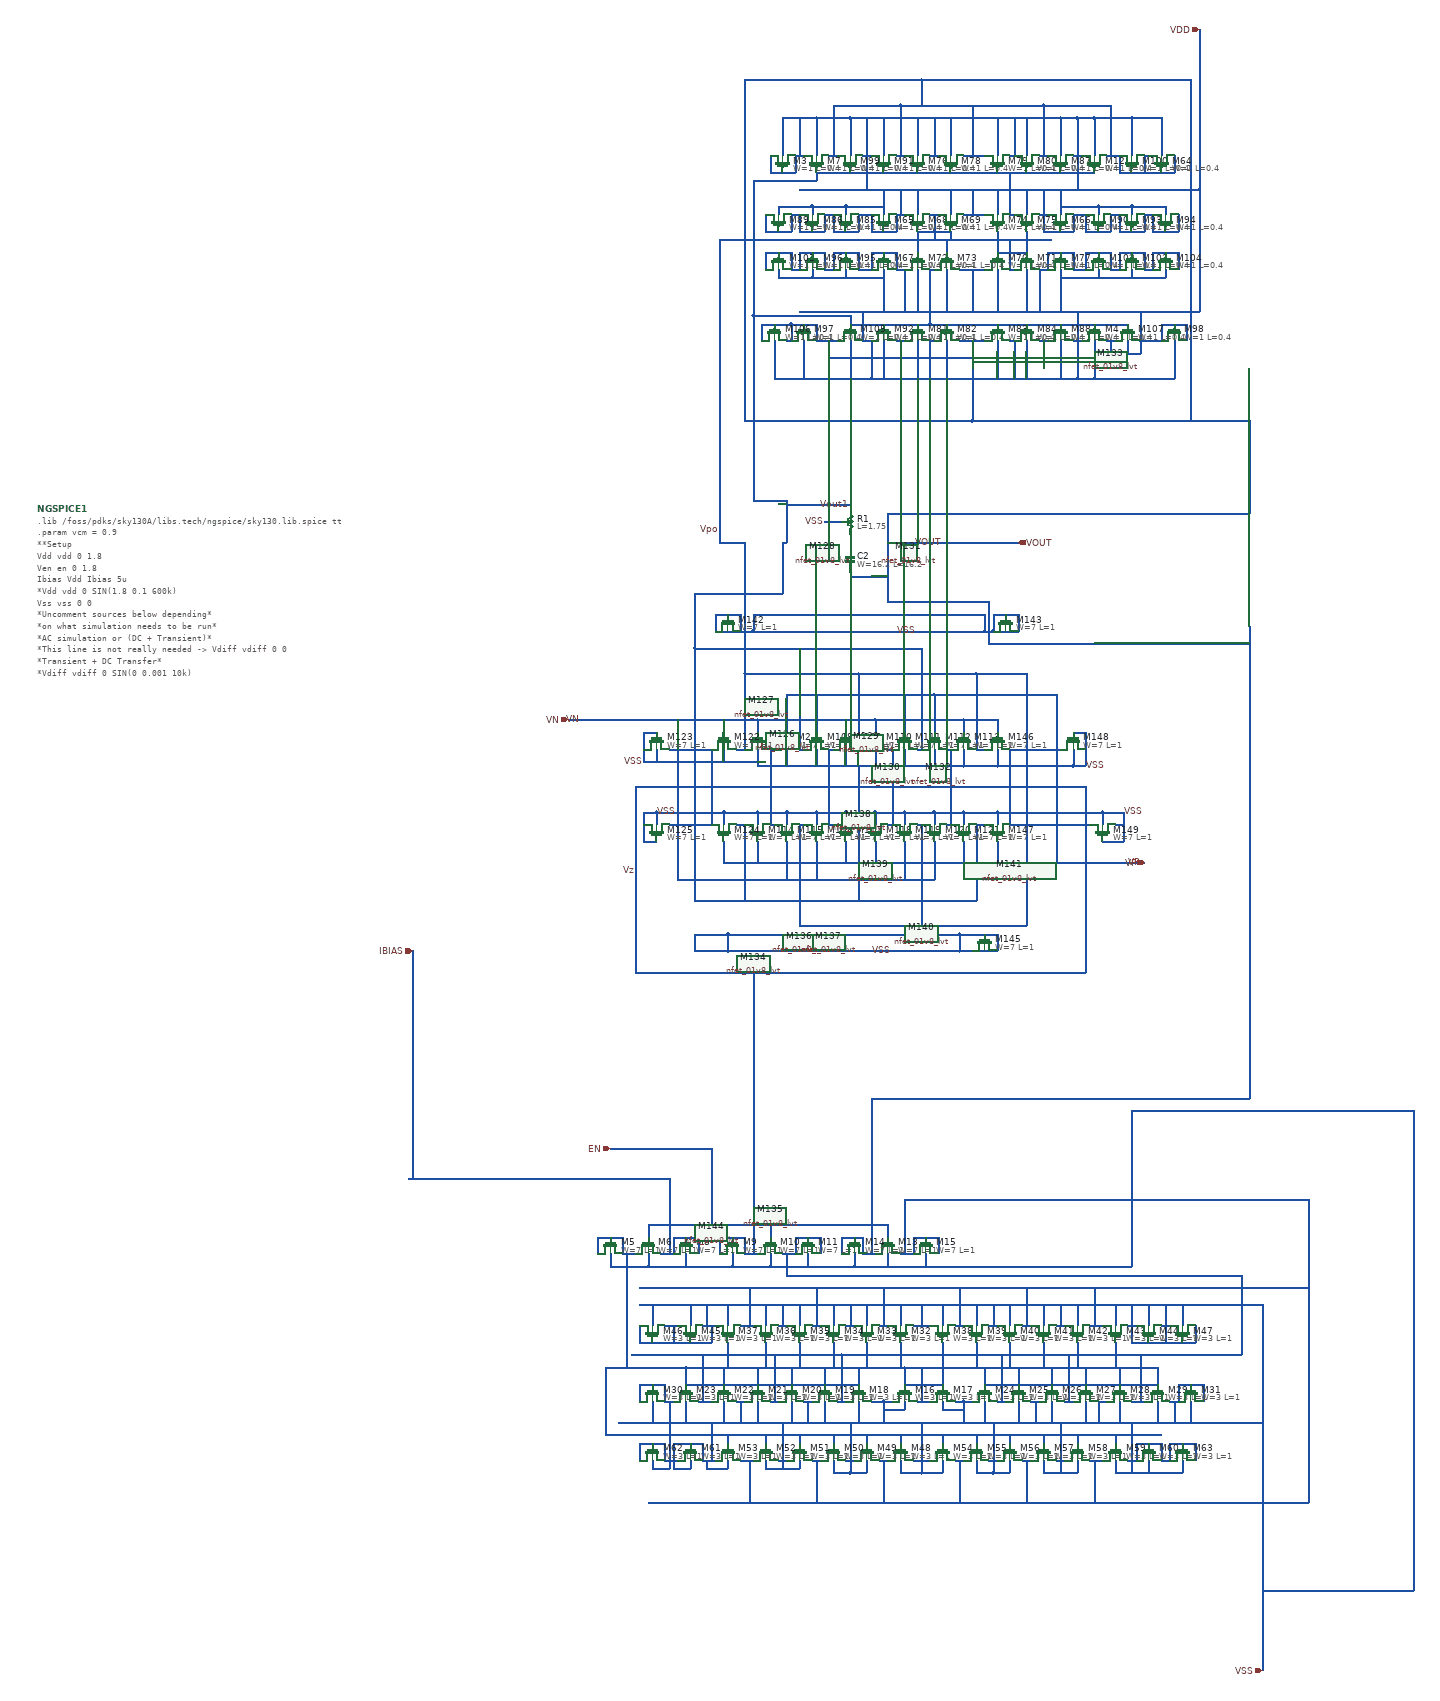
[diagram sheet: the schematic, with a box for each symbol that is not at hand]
v {xschem version=3.4.8RC file_version=1.2}
G {}
K {}
V {}
S {}
F {}
E {}
N -560 -780 -560 -720 {lab=Vpo}
N -400 -780 -400 -720 {lab=Vout1}
N -920 -300 -880 -300 {lab=VN}
N -560 -820 -560 -780 {lab=Vpo}
N -400 -820 -400 -780 {lab=Vout1}
N -1290 250 -1290 490 {lab=IBIAS}
N -160 -760 -160 -680 {lab=VOUT}
N -400 -810 -250 -810 {lab=Vout1}
N 70 -720 150 -720 {lab=VOUT}
N -30 -720 70 -720 {lab=VOUT}
N -160 -720 -30 -720 {lab=VOUT}
N -1290 490 -1290 530 {lab=IBIAS}
N -160 -780 -160 -760 {lab=VOUT}
N -160 -680 -160 -630 {lab=VOUT}
N -250 -730 -250 -710 {lab=#net1}
N -250 -650 -250 -640 {lab=VOUT}
N -250 -640 -160 -640 {lab=VOUT}
N -250 -810 -250 -800 {lab=Vout1}
N -250 -740 -250 -730 {lab=#net1}
N 420 40 440 40 {lab=VP}
N 440 40 450 40 {lab=VP}
N -310 -770 -270 -770 {lab=VSS}
N -850 930 -850 970 {lab=#net2}
N -850 930 -820 930 {lab=#net2}
N -820 930 -790 930 {lab=#net2}
N -790 930 -790 970 {lab=#net2}
N -790 970 -760 970 {lab=#net2}
N -700 970 -670 970 {lab=IBIAS}
N -670 930 -670 970 {lab=IBIAS}
N -670 930 -640 930 {lab=IBIAS}
N -640 930 -610 930 {lab=IBIAS}
N -610 930 -610 970 {lab=IBIAS}
N -560 930 -560 970 {lab=Vz}
N -560 930 -530 930 {lab=Vz}
N -530 930 -500 930 {lab=Vz}
N -500 930 -500 970 {lab=Vz}
N -500 970 -470 970 {lab=Vz}
N -410 970 -380 970 {lab=#net3}
N -380 930 -380 970 {lab=#net3}
N -380 930 -350 930 {lab=#net3}
N -350 930 -320 930 {lab=#net3}
N -320 930 -320 970 {lab=#net3}
N -250 930 -220 930 {lab=VOUT}
N -220 930 -220 970 {lab=VOUT}
N -220 970 -190 970 {lab=VOUT}
N -130 970 -100 970 {lab=#net4}
N -100 930 -100 970 {lab=#net4}
N -100 930 -70 930 {lab=#net4}
N -70 930 -40 930 {lab=#net4}
N -40 930 -40 970 {lab=#net4}
N -730 900 -350 900 {lab=EN}
N -350 900 -160 900 {lab=EN}
N -160 900 -160 930 {lab=EN}
N -440 900 -440 930 {lab=EN}
N -90 1320 -60 1320 {lab=#net2}
N -820 720 -730 720 {lab=EN}
N -120 1240 -40 1240 {lab=#net2}
N -30 1240 -30 1280 {lab=#net2}
N -40 1240 -30 1240 {lab=#net2}
N -120 1240 -120 1280 {lab=#net2}
N -80 1240 -80 1320 {lab=#net2}
N -120 1280 -80 1280 {lab=#net2}
N -80 1280 -30 1280 {lab=#net2}
N -170 1320 -150 1320 {lab=VSS}
N 0 1320 20 1320 {lab=VSS}
N -200 1320 -170 1320 {lab=VSS}
N -280 1320 -260 1320 {lab=#net3}
N -360 1320 -340 1320 {lab=VSS}
N -440 1320 -420 1320 {lab=#net3}
N -520 1320 -500 1320 {lab=VSS}
N -610 1320 -580 1320 {lab=#net3}
N -640 1240 -120 1240 {lab=#net2}
N -230 1240 -230 1280 {lab=#net2}
N -310 1240 -310 1280 {lab=#net2}
N -390 1240 -390 1280 {lab=#net2}
N -470 1240 -470 1280 {lab=#net2}
N -550 1240 -550 1280 {lab=#net2}
N -640 1240 -640 1280 {lab=#net2}
N -640 1280 -230 1280 {lab=#net2}
N -270 1210 -270 1320 {lab=#net3}
N -330 1210 -270 1210 {lab=#net3}
N 20 1320 40 1320 {lab=VSS}
N 100 1320 120 1320 {lab=#net3}
N 180 1320 200 1320 {lab=VSS}
N 260 1320 280 1320 {lab=#net3}
N 340 1320 360 1320 {lab=VSS}
N 420 1320 450 1320 {lab=#net3}
N -270 1210 500 1210 {lab=#net3}
N -770 1210 -330 1210 {lab=#net3}
N 110 1210 110 1320 {lab=#net3}
N -120 840 -120 970 {lab=#net4}
N -120 840 250 840 {lab=#net4}
N -600 1210 -600 1320 {lab=#net3}
N 440 1210 440 1320 {lab=#net3}
N -30 1240 480 1240 {lab=#net2}
N 480 1240 480 1280 {lab=#net2}
N 390 1240 390 1280 {lab=#net2}
N 310 1240 310 1280 {lab=#net2}
N 230 1240 230 1280 {lab=#net2}
N 150 1240 150 1280 {lab=#net2}
N 70 1250 70 1280 {lab=#net2}
N 70 1240 70 1250 {lab=#net2}
N 70 1280 480 1280 {lab=#net2}
N -430 1210 -430 1320 {lab=#net3}
N 270 1210 270 1320 {lab=#net3}
N -690 1320 -670 1320 {lab=VSS}
N -690 1280 -690 1320 {lab=VSS}
N -720 1280 -690 1280 {lab=VSS}
N -750 1280 -720 1280 {lab=VSS}
N -750 1280 -750 1320 {lab=VSS}
N 510 1320 530 1320 {lab=VSS}
N 530 1280 530 1320 {lab=VSS}
N 530 1280 560 1280 {lab=VSS}
N 560 1280 590 1280 {lab=VSS}
N 590 1280 590 1320 {lab=VSS}
N -830 1240 -640 1240 {lab=#net2}
N -830 1240 -830 1400 {lab=#net2}
N -830 1400 490 1400 {lab=#net2}
N -730 900 -730 930 {lab=EN}
N -480 620 -480 970 {lab=Vz}
N -200 600 -200 970 {lab=VOUT}
N -580 720 -580 900 {lab=EN}
N -730 720 -580 720 {lab=EN}
N -1300 790 -680 790 {lab=IBIAS}
N -680 790 -680 970 {lab=IBIAS}
N -780 970 -780 1240 {lab=#net2}
N -540 1180 -540 1240 {lab=#net2}
N -450 1180 -450 1240 {lab=#net2}
N -370 1180 -370 1240 {lab=#net2}
N -290 1180 -290 1240 {lab=#net2}
N -210 1180 -210 1240 {lab=#net2}
N -130 1180 -130 1240 {lab=#net2}
N -30 1180 -30 1240 {lab=#net2}
N 50 1180 50 1240 {lab=#net2}
N 130 1180 130 1240 {lab=#net2}
N 210 1180 210 1240 {lab=#net2}
N 290 1180 290 1240 {lab=#net2}
N 380 1180 380 1240 {lab=#net2}
N -540 1400 -540 1420 {lab=#net2}
N -450 1400 -450 1420 {lab=#net2}
N -370 1400 -370 1420 {lab=#net2}
N -290 1400 -290 1420 {lab=#net2}
N -210 1400 -210 1420 {lab=#net2}
N -130 1400 -130 1420 {lab=#net2}
N -30 1400 -30 1420 {lab=#net2}
N 50 1400 50 1420 {lab=#net2}
N 130 1400 130 1420 {lab=#net2}
N 210 1400 210 1420 {lab=#net2}
N 290 1400 290 1420 {lab=#net2}
N 380 1400 380 1420 {lab=#net2}
N -690 1140 -660 1140 {lab=VSS}
N -600 1140 -570 1140 {lab=VSS}
N -510 1140 -480 1140 {lab=#net4}
N -420 1140 -400 1140 {lab=VSS}
N -340 1140 -320 1140 {lab=#net4}
N -260 1140 -240 1140 {lab=VSS}
N -180 1140 -160 1140 {lab=#net4}
N -100 1140 -60 1140 {lab=VSS}
N 0 1140 20 1140 {lab=#net4}
N 80 1140 100 1140 {lab=VSS}
N 160 1140 180 1140 {lab=#net4}
N 240 1140 260 1140 {lab=VSS}
N 320 1140 350 1140 {lab=#net4}
N 410 1140 430 1140 {lab=VSS}
N 490 1140 510 1140 {lab=VSS}
N 420 1140 420 1180 {lab=VSS}
N 420 1180 460 1180 {lab=VSS}
N 460 1180 500 1180 {lab=VSS}
N 500 1140 500 1180 {lab=VSS}
N 500 1180 540 1180 {lab=VSS}
N 540 1180 570 1180 {lab=VSS}
N 570 1140 570 1180 {lab=VSS}
N 490 1460 510 1460 {lab=VSS}
N 510 1420 510 1460 {lab=VSS}
N 510 1420 540 1420 {lab=VSS}
N 540 1420 570 1420 {lab=VSS}
N 570 1420 570 1460 {lab=VSS}
N 490 1420 490 1460 {lab=VSS}
N 460 1420 490 1420 {lab=VSS}
N 430 1420 460 1420 {lab=VSS}
N 430 1420 430 1460 {lab=VSS}
N 410 1460 430 1460 {lab=VSS}
N 320 1460 350 1460 {lab=#net4}
N 240 1460 260 1460 {lab=VSS}
N 160 1460 180 1460 {lab=#net4}
N 80 1460 100 1460 {lab=VSS}
N 0 1460 20 1460 {lab=#net4}
N -100 1460 -60 1460 {lab=VSS}
N -180 1460 -160 1460 {lab=#net4}
N -260 1460 -240 1460 {lab=VSS}
N -340 1460 -320 1460 {lab=#net4}
N -420 1460 -400 1460 {lab=VSS}
N -510 1460 -480 1460 {lab=#net4}
N -600 1460 -570 1460 {lab=VSS}
N -690 1460 -660 1460 {lab=VSS}
N -600 1420 -600 1460 {lab=VSS}
N -630 1420 -600 1420 {lab=VSS}
N -670 1420 -630 1420 {lab=VSS}
N -670 1420 -670 1460 {lab=VSS}
N -690 1420 -690 1460 {lab=VSS}
N -720 1420 -690 1420 {lab=VSS}
N -750 1420 -720 1420 {lab=VSS}
N -750 1420 -750 1460 {lab=VSS}
N -800 1370 730 1370 {lab=VSS}
N -680 1320 -680 1370 {lab=VSS}
N -680 1370 -680 1460 {lab=VSS}
N -720 1320 -720 1370 {lab=VSS}
N -640 1320 -640 1370 {lab=VSS}
N -550 1320 -550 1370 {lab=VSS}
N -510 1320 -510 1370 {lab=VSS}
N -470 1320 -470 1370 {lab=VSS}
N -750 1140 -750 1180 {lab=VSS}
N -750 1180 -720 1180 {lab=VSS}
N -720 1180 -670 1180 {lab=VSS}
N -670 1140 -670 1180 {lab=VSS}
N -680 1180 -630 1180 {lab=VSS}
N -630 1180 -580 1180 {lab=VSS}
N -580 1140 -580 1180 {lab=VSS}
N -720 1460 -720 1480 {lab=VSS}
N -720 1480 -680 1480 {lab=VSS}
N -680 1460 -680 1480 {lab=VSS}
N -630 1460 -630 1480 {lab=VSS}
N -670 1480 -630 1480 {lab=VSS}
N -670 1460 -670 1480 {lab=VSS}
N -540 1460 -540 1480 {lab=VSS}
N -590 1480 -540 1480 {lab=VSS}
N -590 1460 -590 1480 {lab=VSS}
N -580 1370 -580 1460 {lab=VSS}
N -450 1460 -450 1480 {lab=VSS}
N -450 1480 -410 1480 {lab=VSS}
N -410 1460 -410 1480 {lab=VSS}
N -410 1370 -410 1460 {lab=VSS}
N -350 1320 -350 1370 {lab=VSS}
N -390 1320 -390 1370 {lab=VSS}
N -370 1460 -370 1480 {lab=VSS}
N -410 1480 -370 1480 {lab=VSS}
N -250 1370 -250 1460 {lab=VSS}
N -310 1320 -310 1370 {lab=VSS}
N -250 1460 -250 1490 {lab=VSS}
N -290 1490 -250 1490 {lab=VSS}
N -290 1460 -290 1490 {lab=VSS}
N -250 1490 -210 1490 {lab=VSS}
N -210 1460 -210 1490 {lab=VSS}
N -230 1320 -230 1370 {lab=VSS}
N -170 1320 -170 1370 {lab=VSS}
N -120 1320 -120 1340 {lab=VSS}
N -170 1340 -120 1340 {lab=VSS}
N -80 1370 -80 1460 {lab=VSS}
N -130 1460 -130 1490 {lab=VSS}
N -130 1490 -80 1490 {lab=VSS}
N -80 1460 -80 1490 {lab=VSS}
N -80 1490 -30 1490 {lab=VSS}
N -30 1460 -30 1490 {lab=VSS}
N -30 1320 -30 1340 {lab=VSS}
N -30 1340 20 1340 {lab=VSS}
N 20 1320 20 1340 {lab=VSS}
N 20 1340 20 1370 {lab=VSS}
N 90 1370 90 1460 {lab=VSS}
N 50 1460 50 1490 {lab=VSS}
N 50 1490 90 1490 {lab=VSS}
N 90 1460 90 1490 {lab=VSS}
N 130 1460 130 1490 {lab=VSS}
N 90 1490 130 1490 {lab=VSS}
N 70 1320 70 1370 {lab=VSS}
N 190 1320 190 1370 {lab=VSS}
N 150 1320 150 1370 {lab=VSS}
N 250 1370 250 1460 {lab=VSS}
N 210 1460 210 1490 {lab=VSS}
N 210 1490 290 1490 {lab=VSS}
N 290 1460 290 1490 {lab=VSS}
N 250 1460 250 1490 {lab=VSS}
N 230 1320 230 1370 {lab=VSS}
N 310 1320 310 1370 {lab=VSS}
N 390 1320 390 1370 {lab=VSS}
N 480 1320 480 1370 {lab=VSS}
N 520 1320 520 1370 {lab=VSS}
N 340 1320 340 1370 {lab=VSS}
N 420 1370 420 1460 {lab=VSS}
N 380 1460 380 1490 {lab=VSS}
N 380 1490 540 1490 {lab=VSS}
N 540 1460 540 1490 {lab=VSS}
N 460 1460 460 1490 {lab=VSS}
N -750 1090 660 1090 {lab=VSS}
N 730 1090 730 1370 {lab=VSS}
N 660 1090 730 1090 {lab=VSS}
N 730 1370 730 1900 {lab=VSS}
N -720 1090 -720 1140 {lab=VSS}
N -590 1090 -590 1140 {lab=VSS}
N -630 1090 -630 1140 {lab=VSS}
N -540 1090 -540 1140 {lab=VSS}
N -410 1090 -410 1140 {lab=VSS}
N -450 1090 -450 1140 {lab=VSS}
N -370 1090 -370 1140 {lab=VSS}
N -290 1090 -290 1140 {lab=VSS}
N -250 1090 -250 1140 {lab=VSS}
N -210 1090 -210 1140 {lab=VSS}
N -130 1090 -130 1140 {lab=VSS}
N -80 1090 -80 1140 {lab=VSS}
N -30 1090 -30 1140 {lab=VSS}
N 50 1090 50 1140 {lab=VSS}
N 90 1090 90 1140 {lab=VSS}
N 130 1090 130 1140 {lab=VSS}
N 210 1090 210 1140 {lab=VSS}
N 250 1090 250 1140 {lab=VSS}
N 290 1090 290 1140 {lab=VSS}
N 380 1090 380 1140 {lab=VSS}
N 420 1090 420 1140 {lab=VSS}
N 460 1090 460 1140 {lab=VSS}
N 500 1090 500 1140 {lab=VSS}
N 540 1090 540 1140 {lab=VSS}
N 500 1210 660 1210 {lab=#net3}
N -400 1020 660 1020 {lab=#net3}
N -400 970 -400 1020 {lab=#net3}
N -730 1560 840 1560 {lab=#net4}
N 840 840 840 1560 {lab=#net4}
N 250 840 840 840 {lab=#net4}
N -750 1050 840 1050 {lab=#net4}
N -490 1050 -490 1140 {lab=#net4}
N -330 1050 -330 1140 {lab=#net4}
N -170 1050 -170 1140 {lab=#net4}
N 10 1050 10 1140 {lab=#net4}
N 170 1050 170 1140 {lab=#net4}
N 330 1050 330 1140 {lab=#net4}
N -490 1460 -490 1560 {lab=#net4}
N -330 1460 -330 1560 {lab=#net4}
N -170 1460 -170 1560 {lab=#net4}
N 10 1460 10 1560 {lab=#net4}
N 170 1460 170 1560 {lab=#net4}
N 330 1460 330 1560 {lab=#net4}
N -160 -630 -160 -600 {lab=VOUT}
N -200 600 -160 600 {lab=VOUT}
N -1290 530 -1290 790 {lab=IBIAS}
N 1090 630 1090 1770 {lab=VSS}
N 730 1770 1090 1770 {lab=VSS}
N -820 970 -820 1000 {lab=VSS}
N -820 1000 -730 1000 {lab=VSS}
N -730 970 -730 1000 {lab=VSS}
N -730 1000 -640 1000 {lab=VSS}
N -640 970 -640 1000 {lab=VSS}
N -640 1000 -530 1000 {lab=VSS}
N -530 970 -530 1000 {lab=VSS}
N -530 1000 -440 1000 {lab=VSS}
N -440 970 -440 1000 {lab=VSS}
N -440 1000 -350 1000 {lab=VSS}
N -350 970 -350 1000 {lab=VSS}
N -350 1000 -240 1000 {lab=VSS}
N -240 970 -240 1000 {lab=VSS}
N -240 1000 -160 1000 {lab=VSS}
N -160 970 -160 1000 {lab=VSS}
N -160 1000 -70 1000 {lab=VSS}
N -70 970 -70 1000 {lab=VSS}
N -70 1000 420 1000 {lab=VSS}
N 420 630 420 1000 {lab=VSS}
N 420 1460 420 1490 {lab=VSS}
N 560 1320 560 1370 {lab=VSS}
N 660 1210 680 1210 {lab=#net3}
N 680 1020 680 1210 {lab=#net3}
N 660 1020 680 1020 {lab=#net3}
N -270 930 -270 970 {lab=VOUT}
N -270 930 -250 930 {lab=VOUT}
N -60 -1500 -40 -1500 {lab=Vpo}
N 130 -1370 140 -1370 {lab=Vpo}
N -140 -1440 230 -1440 {lab=Vpo}
N 100 -1440 100 -1420 {lab=Vpo}
N -90 -1460 -90 -1440 {lab=Vpo}
N -90 -1440 -90 -1410 {lab=Vpo}
N -20 -1440 -20 -1410 {lab=Vpo}
N -370 -1560 580 -1560 {lab=VDD}
N -370 -1270 580 -1270 {lab=VDD}
N 580 -1560 580 -1270 {lab=VDD}
N 580 -1940 580 -1560 {lab=VDD}
N 100 -1460 100 -1440 {lab=Vpo}
N 170 -1460 170 -1440 {lab=Vpo}
N 170 -1440 170 -1420 {lab=Vpo}
N 130 -1500 140 -1500 {lab=Vout1}
N -60 -1370 -50 -1370 {lab=Vout1}
N 20 -1500 70 -1500 {lab=VDD}
N 40 -1560 40 -1500 {lab=VDD}
N -50 -1500 -50 -1460 {lab=Vpo}
N -50 -1460 -10 -1460 {lab=Vpo}
N -90 -1460 -50 -1460 {lab=Vpo}
N 100 -1560 100 -1500 {lab=VDD}
N 170 -1560 170 -1500 {lab=VDD}
N 100 -1420 100 -1410 {lab=Vpo}
N 170 -1420 170 -1410 {lab=Vpo}
N -90 -1370 -90 -1270 {lab=VDD}
N -20 -1370 -20 -1270 {lab=VDD}
N 100 -1370 100 -1270 {lab=VDD}
N 170 -1370 170 -1270 {lab=VDD}
N 10 -1370 60 -1370 {lab=VDD}
N 60 -1370 70 -1370 {lab=VDD}
N 40 -1370 40 -1270 {lab=VDD}
N 100 -1410 170 -1410 {lab=Vpo}
N -10 -1460 -10 -1440 {lab=Vpo}
N -560 -1310 -560 -980 {lab=Vpo}
N 130 -1600 130 -1500 {lab=Vout1}
N -170 -1600 -90 -1600 {lab=Vout1}
N -90 -1600 -10 -1600 {lab=Vout1}
N -10 -1600 100 -1600 {lab=Vout1}
N 100 -1600 170 -1600 {lab=Vout1}
N 170 -1600 250 -1600 {lab=Vout1}
N -60 -1370 -60 -1240 {lab=Vout1}
N -170 -1240 -90 -1240 {lab=Vout1}
N -90 -1240 -60 -1240 {lab=Vout1}
N -60 -1240 -20 -1240 {lab=Vout1}
N -20 -1240 100 -1240 {lab=Vout1}
N 100 -1240 170 -1240 {lab=Vout1}
N 170 -1240 250 -1240 {lab=Vout1}
N -170 -1200 -170 -1110 {lab=VDD}
N -170 -1110 250 -1110 {lab=VDD}
N 250 -1200 250 -1110 {lab=VDD}
N 170 -1200 170 -1110 {lab=VDD}
N 100 -1200 100 -1110 {lab=VDD}
N -20 -1200 -20 -1110 {lab=VDD}
N -90 -1200 -90 -1110 {lab=VDD}
N -330 -1200 -290 -1200 {lab=VOUT}
N -330 -1240 -330 -1200 {lab=VOUT}
N -360 -1240 -330 -1240 {lab=VOUT}
N -390 -1240 -360 -1240 {lab=VOUT}
N -390 -1240 -390 -1200 {lab=VOUT}
N -220 -1270 -220 -1200 {lab=VDD}
N -200 -1200 -200 -1110 {lab=VDD}
N -200 -1110 -170 -1110 {lab=VDD}
N 470 -1200 490 -1200 {lab=VDD}
N 290 -1200 290 -1110 {lab=VDD}
N 250 -1110 290 -1110 {lab=VDD}
N 490 -1240 490 -1200 {lab=VDD}
N 490 -1240 520 -1240 {lab=VDD}
N 520 -1240 550 -1240 {lab=VDD}
N 550 -1240 550 -1200 {lab=VDD}
N 290 -1270 290 -1200 {lab=VDD}
N 10 -1200 70 -1200 {lab=VOUT}
N 40 -1200 40 -1010 {lab=VOUT}
N 40 -1010 700 -1010 {lab=VOUT}
N -140 -1200 -120 -1200 {lab=VOUT}
N 130 -1200 140 -1200 {lab=VDD}
N 200 -1200 220 -1200 {lab=VOUT}
N 140 -1200 140 -1110 {lab=VDD}
N -60 -1200 -50 -1200 {lab=VDD}
N -60 -1200 -60 -1110 {lab=VDD}
N -130 -1200 -130 -1160 {lab=VOUT}
N -130 -1160 40 -1160 {lab=VOUT}
N 210 -1200 210 -1150 {lab=VOUT}
N 40 -1150 210 -1150 {lab=VOUT}
N 520 -1200 520 -1110 {lab=VDD}
N 480 -1110 520 -1110 {lab=VDD}
N -360 -1200 -360 -1110 {lab=VDD}
N -360 -1110 -290 -1110 {lab=VDD}
N 360 -1640 390 -1640 {lab=VOUT}
N 390 -1640 390 -1600 {lab=VOUT}
N 390 -1600 420 -1600 {lab=VOUT}
N 420 -1600 450 -1600 {lab=VOUT}
N 450 -1640 450 -1600 {lab=VOUT}
N -220 -1640 -200 -1640 {lab=VDD}
N -210 -1640 -210 -1560 {lab=VDD}
N -250 -1600 -220 -1600 {lab=Vout1}
N -250 -1730 -250 -1640 {lab=VDD}
N -250 -1730 250 -1730 {lab=VDD}
N 250 -1730 250 -1640 {lab=VDD}
N 290 -1730 290 -1640 {lab=VDD}
N 250 -1730 290 -1730 {lab=VDD}
N 290 -1640 290 -1560 {lab=VDD}
N 420 -1730 420 -1640 {lab=VDD}
N 200 -1640 220 -1640 {lab=VOUT}
N 130 -1640 140 -1640 {lab=VDD}
N 140 -1730 140 -1640 {lab=VDD}
N 20 -1640 70 -1640 {lab=VOUT}
N -60 -1640 -40 -1640 {lab=VDD}
N -50 -1730 -50 -1640 {lab=VDD}
N -90 -1730 -90 -1640 {lab=VDD}
N -10 -1730 -10 -1640 {lab=VDD}
N 100 -1730 100 -1640 {lab=VDD}
N 170 -1730 170 -1640 {lab=VDD}
N -170 -1730 -170 -1640 {lab=VDD}
N -210 -1730 -210 -1640 {lab=VDD}
N -140 -1640 -120 -1640 {lab=VOUT}
N -130 -1760 -130 -1640 {lab=VOUT}
N -130 -1760 210 -1760 {lab=VOUT}
N 210 -1760 210 -1640 {lab=VOUT}
N 40 -1760 40 -1640 {lab=VOUT}
N -80 -1820 -80 -1760 {lab=VOUT}
N -430 -1820 -80 -1820 {lab=VOUT}
N -430 -1010 40 -1010 {lab=VOUT}
N -80 -1820 530 -1820 {lab=VOUT}
N -190 -1600 -170 -1600 {lab=Vout1}
N 250 -1600 270 -1600 {lab=Vout1}
N 250 -1240 270 -1240 {lab=Vout1}
N -560 -980 -560 -870 {lab=Vpo}
N 130 -1410 130 -1370 {lab=Vpo}
N -120 -1370 -120 -1270 {lab=VDD}
N -220 -1600 -190 -1600 {lab=Vout1}
N -300 -1640 -280 -1640 {lab=VOUT}
N -330 -1600 -250 -1600 {lab=Vout1}
N -330 -1730 -330 -1640 {lab=VDD}
N -330 -1730 -250 -1730 {lab=VDD}
N -380 -1640 -360 -1640 {lab=VDD}
N -380 -1640 -380 -1600 {lab=VDD}
N -410 -1600 -380 -1600 {lab=VDD}
N -440 -1600 -410 -1600 {lab=VDD}
N -440 -1640 -440 -1600 {lab=VDD}
N -410 -1730 -410 -1640 {lab=VDD}
N -410 -1730 -330 -1730 {lab=VDD}
N -370 -1730 -370 -1640 {lab=VDD}
N -500 -1820 -500 -1010 {lab=VOUT}
N -500 -1010 -430 -1010 {lab=VOUT}
N -500 -1820 -430 -1820 {lab=VOUT}
N 280 -1640 300 -1640 {lab=VDD}
N 270 -1600 330 -1600 {lab=Vout1}
N 450 -1640 460 -1640 {lab=VOUT}
N 450 -1600 490 -1600 {lab=VOUT}
N 490 -1600 520 -1600 {lab=VOUT}
N 520 -1640 520 -1600 {lab=VOUT}
N 490 -1730 490 -1640 {lab=VDD}
N 420 -1730 490 -1730 {lab=VDD}
N -560 -1440 -140 -1440 {lab=Vpo}
N -560 -1440 -560 -1310 {lab=Vpo}
N 130 -1440 130 -1410 {lab=Vpo}
N -50 -1460 -50 -1440 {lab=Vpo}
N -90 -1560 -90 -1500 {lab=VDD}
N -140 -1500 -120 -1500 {lab=VDD}
N -140 -1500 -140 -1460 {lab=VDD}
N -170 -1460 -140 -1460 {lab=VDD}
N -200 -1460 -170 -1460 {lab=VDD}
N -200 -1500 -200 -1460 {lab=VDD}
N 200 -1500 220 -1500 {lab=VDD}
N 210 -1500 210 -1460 {lab=VDD}
N 210 -1460 250 -1460 {lab=VDD}
N 250 -1460 280 -1460 {lab=VDD}
N 280 -1500 280 -1460 {lab=VDD}
N -130 -1560 -130 -1500 {lab=VDD}
N 210 -1560 210 -1500 {lab=VDD}
N 250 -1560 250 -1500 {lab=VDD}
N -170 -1560 -170 -1500 {lab=VDD}
N -140 -1370 -120 -1370 {lab=VDD}
N -140 -1410 -140 -1370 {lab=VDD}
N -170 -1410 -140 -1410 {lab=VDD}
N -200 -1410 -170 -1410 {lab=VDD}
N -200 -1410 -200 -1370 {lab=VDD}
N -170 -1370 -170 -1270 {lab=VDD}
N 200 -1370 220 -1370 {lab=VDD}
N 220 -1410 220 -1370 {lab=VDD}
N 220 -1410 250 -1410 {lab=VDD}
N 250 -1410 280 -1410 {lab=VDD}
N 280 -1410 280 -1370 {lab=VDD}
N 250 -1370 250 -1280 {lab=VDD}
N 250 -1280 250 -1270 {lab=VDD}
N -230 -1500 -200 -1500 {lab=VDD}
N -230 -1500 -230 -1460 {lab=VDD}
N -260 -1460 -230 -1460 {lab=VDD}
N -290 -1460 -260 -1460 {lab=VDD}
N -290 -1500 -290 -1460 {lab=VDD}
N -310 -1500 -290 -1500 {lab=VDD}
N -310 -1500 -310 -1460 {lab=VDD}
N -340 -1460 -310 -1460 {lab=VDD}
N -370 -1460 -340 -1460 {lab=VDD}
N -370 -1500 -370 -1460 {lab=VDD}
N -390 -1500 -370 -1500 {lab=VDD}
N -390 -1500 -390 -1460 {lab=VDD}
N -420 -1460 -390 -1460 {lab=VDD}
N -450 -1460 -420 -1460 {lab=VDD}
N -450 -1500 -450 -1460 {lab=VDD}
N -420 -1520 -420 -1500 {lab=VDD}
N -420 -1520 -340 -1520 {lab=VDD}
N -340 -1520 -340 -1500 {lab=VDD}
N -340 -1520 -260 -1520 {lab=VDD}
N -260 -1520 -260 -1500 {lab=VDD}
N -260 -1520 -170 -1520 {lab=VDD}
N 280 -1500 310 -1500 {lab=VDD}
N 310 -1500 310 -1460 {lab=VDD}
N 310 -1460 340 -1460 {lab=VDD}
N 340 -1460 370 -1460 {lab=VDD}
N 370 -1500 370 -1460 {lab=VDD}
N 370 -1500 390 -1500 {lab=VDD}
N 390 -1500 390 -1460 {lab=VDD}
N 390 -1460 420 -1460 {lab=VDD}
N 420 -1460 450 -1460 {lab=VDD}
N 450 -1500 450 -1460 {lab=VDD}
N 450 -1500 470 -1500 {lab=VDD}
N 470 -1500 470 -1460 {lab=VDD}
N 470 -1460 500 -1460 {lab=VDD}
N 500 -1460 530 -1460 {lab=VDD}
N 530 -1500 530 -1460 {lab=VDD}
N 500 -1520 500 -1500 {lab=VDD}
N 420 -1520 500 -1520 {lab=VDD}
N 420 -1520 420 -1500 {lab=VDD}
N 340 -1520 420 -1520 {lab=VDD}
N 340 -1520 340 -1500 {lab=VDD}
N 250 -1520 340 -1520 {lab=VDD}
N 560 -1820 560 -1010 {lab=VOUT}
N 530 -1820 560 -1820 {lab=VOUT}
N -230 -1370 -200 -1370 {lab=VDD}
N -230 -1410 -230 -1370 {lab=VDD}
N -260 -1410 -230 -1410 {lab=VDD}
N -290 -1410 -260 -1410 {lab=VDD}
N -290 -1410 -290 -1370 {lab=VDD}
N -310 -1370 -290 -1370 {lab=VDD}
N -310 -1410 -310 -1370 {lab=VDD}
N -340 -1410 -310 -1410 {lab=VDD}
N -370 -1410 -340 -1410 {lab=VDD}
N -370 -1410 -370 -1370 {lab=VDD}
N -390 -1370 -370 -1370 {lab=VDD}
N -390 -1410 -390 -1370 {lab=VDD}
N -420 -1410 -390 -1410 {lab=VDD}
N -450 -1410 -420 -1410 {lab=VDD}
N -450 -1410 -450 -1370 {lab=VDD}
N -420 -1370 -420 -1350 {lab=VDD}
N -420 -1350 -340 -1350 {lab=VDD}
N -340 -1370 -340 -1350 {lab=VDD}
N -340 -1350 -260 -1350 {lab=VDD}
N -260 -1370 -260 -1350 {lab=VDD}
N -260 -1350 -170 -1350 {lab=VDD}
N 310 -1410 310 -1370 {lab=VDD}
N 310 -1410 340 -1410 {lab=VDD}
N 340 -1410 370 -1410 {lab=VDD}
N 370 -1410 370 -1370 {lab=VDD}
N 370 -1370 390 -1370 {lab=VDD}
N 390 -1410 390 -1370 {lab=VDD}
N 390 -1410 420 -1410 {lab=VDD}
N 420 -1410 450 -1410 {lab=VDD}
N 450 -1410 450 -1370 {lab=VDD}
N 450 -1370 470 -1370 {lab=VDD}
N 470 -1410 470 -1370 {lab=VDD}
N 470 -1410 500 -1410 {lab=VDD}
N 500 -1410 530 -1410 {lab=VDD}
N 530 -1410 530 -1370 {lab=VDD}
N 500 -1370 500 -1350 {lab=VDD}
N 420 -1350 500 -1350 {lab=VDD}
N 420 -1370 420 -1350 {lab=VDD}
N 340 -1350 420 -1350 {lab=VDD}
N 340 -1370 340 -1350 {lab=VDD}
N 250 -1350 340 -1350 {lab=VDD}
N 280 -1370 310 -1370 {lab=VDD}
N -220 -1200 -200 -1200 {lab=VDD}
N -290 -1200 -280 -1200 {lab=VOUT}
N -290 -1110 -200 -1110 {lab=VDD}
N -430 -1240 -390 -1240 {lab=VOUT}
N -400 -1200 -390 -1200 {lab=VOUT}
N -460 -1240 -460 -1200 {lab=VOUT}
N -460 -1240 -430 -1240 {lab=VOUT}
N -430 -1200 -430 -1110 {lab=VDD}
N -430 -1110 -360 -1110 {lab=VDD}
N -290 -1760 -290 -1640 {lab=VOUT}
N -290 -1760 -130 -1760 {lab=VOUT}
N 210 -1760 370 -1760 {lab=VOUT}
N -300 -1200 -300 -1160 {lab=VOUT}
N -300 -1160 -130 -1160 {lab=VOUT}
N 280 -1200 300 -1200 {lab=VDD}
N 330 -1200 330 -1110 {lab=VDD}
N 290 -1110 330 -1110 {lab=VDD}
N 270 -1240 330 -1240 {lab=Vout1}
N -250 -1240 -170 -1240 {lab=Vout1}
N 360 -1200 380 -1200 {lab=VOUT}
N 440 -1270 440 -1200 {lab=VDD}
N 410 -1200 410 -1170 {lab=VDD}
N 410 -1170 440 -1170 {lab=VDD}
N 440 -1200 440 -1170 {lab=VDD}
N 440 -1200 470 -1200 {lab=VDD}
N 330 -1110 480 -1110 {lab=VDD}
N 370 -1200 370 -1150 {lab=VOUT}
N 210 -1150 370 -1150 {lab=VOUT}
N 330 -1240 410 -1240 {lab=Vout1}
N -560 -870 -560 -820 {lab=Vpo}
N -330 -1600 -330 -1580 {lab=Vout1}
N -250 -1260 -250 -1240 {lab=Vout1}
N -480 -1260 -250 -1260 {lab=Vout1}
N -480 -1580 -480 -1260 {lab=Vout1}
N -480 -1580 -330 -1580 {lab=Vout1}
N -480 -1260 -480 -820 {lab=Vout1}
N -480 -820 -400 -820 {lab=Vout1}
N 700 -1010 700 -790 {lab=VOUT}
N -160 -790 700 -790 {lab=VOUT}
N -160 -790 -160 -780 {lab=VOUT}
N 370 -1760 370 -1640 {lab=VOUT}
N 330 -1730 330 -1640 {lab=VDD}
N 290 -1730 330 -1730 {lab=VDD}
N 330 -1730 420 -1730 {lab=VDD}
N -250 -1200 -250 -1110 {lab=VDD}
N -10 -1560 -10 -1500 {lab=VDD}
N 200 -1370 200 -1270 {lab=VDD}
N -470 -300 -470 -270 {lab=VN}
N -470 -300 -190 -300 {lab=VN}
N -190 -300 -190 -270 {lab=VN}
N -260 -300 -260 -270 {lab=VN}
N -260 -10 -260 40 {lab=VP}
N -260 40 30 40 {lab=VP}
N -190 -10 -190 40 {lab=VP}
N -190 -300 20 -300 {lab=VN}
N 20 -300 20 -270 {lab=VN}
N -470 -10 -470 40 {lab=VP}
N -470 40 -260 40 {lab=VP}
N 20 -10 20 40 {lab=VP}
N -650 -300 -470 -300 {lab=VN}
N 30 40 230 40 {lab=VP}
N -440 -230 -430 -230 {lab=Vz}
N -370 -230 -360 -230 {lab=Vout1}
N -300 -230 -290 -230 {lab=Vz}
N -230 -230 -220 -230 {lab=Vpo}
N -160 -230 -150 -230 {lab=Vz}
N -90 -230 -80 -230 {lab=Vout1}
N -20 -230 -10 -230 {lab=Vz}
N -440 -50 -430 -50 {lab=Vz}
N -300 -50 -290 -50 {lab=Vz}
N -230 -50 -220 -50 {lab=Vout1}
N -160 -50 -150 -50 {lab=Vz}
N -90 -50 -80 -50 {lab=Vpo}
N -20 -50 -10 -50 {lab=Vz}
N -550 80 -400 80 {lab=VN}
N -400 -10 -400 80 {lab=VN}
N -330 -10 -330 80 {lab=VN}
N -400 80 -330 80 {lab=VN}
N -330 80 -120 80 {lab=VN}
N -120 -10 -120 80 {lab=VN}
N -120 80 -50 80 {lab=VN}
N -50 -10 -50 80 {lab=VN}
N -50 -360 100 -360 {lab=VP}
N -50 -360 -50 -270 {lab=VP}
N -120 -360 -120 -270 {lab=VP}
N -120 -360 -50 -360 {lab=VP}
N -330 -360 -120 -360 {lab=VP}
N -330 -360 -330 -270 {lab=VP}
N -400 -360 -330 -360 {lab=VP}
N -400 -360 -400 -270 {lab=VP}
N -230 -410 -230 -230 {lab=Vpo}
N -500 -410 -500 -230 {lab=Vpo}
N 50 -410 50 -230 {lab=Vpo}
N -500 -410 -230 -410 {lab=Vpo}
N -230 -410 50 -410 {lab=Vpo}
N -230 -50 -230 130 {lab=Vout1}
N -500 -50 -500 130 {lab=Vout1}
N 50 -50 50 130 {lab=Vout1}
N -500 130 -230 130 {lab=Vout1}
N -230 130 50 130 {lab=Vout1}
N -500 -640 -500 -410 {lab=Vpo}
N -370 -50 -360 -50 {lab=Vpo}
N -370 -50 -370 190 {lab=Vpo}
N -80 -50 -80 190 {lab=Vpo}
N -370 190 170 190 {lab=Vpo}
N 170 -410 170 190 {lab=Vpo}
N 50 -410 170 -410 {lab=Vpo}
N -80 -470 -80 -230 {lab=Vout1}
N -370 -470 -370 -230 {lab=Vout1}
N -620 -470 -80 -470 {lab=Vout1}
N -620 -470 -620 130 {lab=Vout1}
N -620 130 -500 130 {lab=Vout1}
N -880 -300 -650 -300 {lab=VN}
N 230 40 420 40 {lab=VP}
N -760 -140 310 -140 {lab=Vz}
N -760 -140 -760 300 {lab=Vz}
N -760 300 -230 300 {lab=Vz}
N 310 -140 310 300 {lab=Vz}
N -230 300 310 300 {lab=Vz}
N -620 -600 -620 -470 {lab=Vout1}
N -620 -600 -410 -600 {lab=Vout1}
N -410 -640 -410 -600 {lab=Vout1}
N -440 -230 -440 -140 {lab=Vz}
N -300 -230 -300 -140 {lab=Vz}
N -150 -230 -150 -140 {lab=Vz}
N -10 -230 -10 -140 {lab=Vz}
N -440 -140 -440 -50 {lab=Vz}
N -300 -140 -300 -50 {lab=Vz}
N -150 -140 -150 -60 {lab=Vz}
N -10 -140 -10 -50 {lab=Vz}
N -470 -230 -470 -190 {lab=VSS}
N -470 -190 20 -190 {lab=VSS}
N 20 -230 20 -190 {lab=VSS}
N -50 -230 -50 -190 {lab=VSS}
N -120 -230 -120 -190 {lab=VSS}
N -260 -230 -260 -190 {lab=VSS}
N -330 -230 -330 -190 {lab=VSS}
N -400 -230 -400 -190 {lab=VSS}
N -470 -80 -470 -50 {lab=VSS}
N -470 -80 -400 -80 {lab=VSS}
N -400 -80 -400 -50 {lab=VSS}
N -400 -80 -330 -80 {lab=VSS}
N -330 -80 -330 -50 {lab=VSS}
N -330 -80 -260 -80 {lab=VSS}
N -260 -80 -260 -50 {lab=VSS}
N -260 -80 -190 -80 {lab=VSS}
N -190 -80 -190 -50 {lab=VSS}
N -190 -80 -120 -80 {lab=VSS}
N -120 -80 -120 -50 {lab=VSS}
N -120 -80 -50 -80 {lab=VSS}
N -50 -80 -50 -50 {lab=VSS}
N -50 -80 20 -80 {lab=VSS}
N 20 -80 20 -50 {lab=VSS}
N -560 -720 -500 -720 {lab=Vpo}
N -410 -720 -400 -720 {lab=Vout1}
N -230 -120 -230 -80 {lab=VSS}
N -230 -190 -230 -120 {lab=VSS}
N -480 300 -480 620 {lab=Vz}
N 420 630 920 630 {lab=VSS}
N 920 630 1090 630 {lab=VSS}
N -160 600 300 600 {lab=VOUT}
N 300 600 470 600 {lab=VOUT}
N 470 600 700 600 {lab=VOUT}
N 700 -520 700 600 {lab=VOUT}
N -150 -60 -150 -50 {lab=Vz}
N -190 -230 -190 -190 {lab=VSS}
N -670 -200 -470 -200 {lab=VSS}
N -480 -550 -480 -510 {lab=VSS}
N -480 -550 70 -550 {lab=VSS}
N 70 -550 70 -510 {lab=VSS}
N -480 -510 70 -510 {lab=VSS}
N -540 210 -540 250 {lab=VSS}
N -540 210 10 210 {lab=VSS}
N 10 210 10 250 {lab=VSS}
N -540 250 10 250 {lab=VSS}
N -160 -600 -160 -580 {lab=VOUT}
N -160 -580 80 -580 {lab=VOUT}
N 80 -580 80 -480 {lab=VOUT}
N 80 -480 700 -480 {lab=VOUT}
N -510 -510 -480 -510 {lab=VSS}
N -510 -550 -510 -510 {lab=VSS}
N -540 -550 -510 -550 {lab=VSS}
N -570 -550 -540 -550 {lab=VSS}
N -570 -550 -570 -510 {lab=VSS}
N -570 -510 -540 -510 {lab=VSS}
N -540 -510 -510 -510 {lab=VSS}
N 70 -510 90 -510 {lab=VSS}
N 90 -550 90 -510 {lab=VSS}
N 90 -550 120 -550 {lab=VSS}
N 120 -550 150 -550 {lab=VSS}
N 150 -550 150 -510 {lab=VSS}
N 90 -510 150 -510 {lab=VSS}
N 10 250 40 250 {lab=VSS}
N 10 210 70 210 {lab=VSS}
N 70 210 100 210 {lab=VSS}
N 100 210 100 250 {lab=VSS}
N 40 250 100 250 {lab=VSS}
N -620 250 -540 250 {lab=VSS}
N -620 210 -620 250 {lab=VSS}
N -620 210 -540 210 {lab=VSS}
N -500 -720 -500 -700 {lab=Vpo}
N -410 -660 -410 -640 {lab=Vout1}
N -500 -700 -500 -640 {lab=Vpo}
N -410 -720 -410 -660 {lab=Vout1}
N 730 1900 730 1960 {lab=VSS}
N -660 80 -550 80 {lab=VN}
N -660 -300 -660 80 {lab=VN}
N -520 -230 -500 -230 {lab=Vpo}
N -550 -300 -550 -270 {lab=VN}
N -550 -230 -550 -200 {lab=VSS}
N -580 -230 -580 -140 {lab=Vz}
N -680 -230 -580 -230 {lab=Vz}
N -740 -270 -710 -270 {lab=VSS}
N -740 -270 -740 -230 {lab=VSS}
N -710 -230 -710 -200 {lab=VSS}
N -710 -200 -670 -200 {lab=VSS}
N -740 -230 -740 -200 {lab=VSS}
N -740 -200 -710 -200 {lab=VSS}
N -520 -50 -500 -50 {lab=Vout1}
N -550 -80 -550 -50 {lab=VSS}
N -550 -80 -470 -80 {lab=VSS}
N -580 -140 -580 -50 {lab=Vz}
N -550 -10 -550 40 {lab=VP}
N -550 40 -470 40 {lab=VP}
N -680 -50 -580 -50 {lab=Vz}
N -740 -50 -740 -10 {lab=VSS}
N -740 -10 -710 -10 {lab=VSS}
N -710 -80 -710 -50 {lab=VSS}
N -710 -80 -550 -80 {lab=VSS}
N -740 -80 -740 -50 {lab=VSS}
N -740 -80 -710 -80 {lab=VSS}
N 100 -360 240 -360 {lab=VP}
N 240 -360 240 40 {lab=VP}
N 50 -230 70 -230 {lab=Vpo}
N 100 -300 100 -270 {lab=VN}
N 20 -300 100 -300 {lab=VN}
N 20 -190 100 -190 {lab=VSS}
N 100 -230 100 -190 {lab=VSS}
N 130 -230 130 -140 {lab=Vz}
N 50 -50 70 -50 {lab=Vout1}
N 100 -10 100 40 {lab=VP}
N 130 -140 130 -50 {lab=Vz}
N 100 -80 100 -50 {lab=VSS}
N 20 -80 100 -80 {lab=VSS}
N 130 -230 250 -230 {lab=Vz}
N 280 -270 310 -270 {lab=VSS}
N 310 -270 310 -230 {lab=VSS}
N 280 -230 280 -190 {lab=VSS}
N 100 -190 280 -190 {lab=VSS}
N 310 -230 310 -190 {lab=VSS}
N 280 -190 310 -190 {lab=VSS}
N 130 -50 320 -50 {lab=Vz}
N 350 -70 350 -50 {lab=VSS}
N 100 -80 350 -80 {lab=VSS}
N 350 -80 350 -70 {lab=VSS}
N 380 -50 400 -50 {lab=VSS}
N 400 -50 400 -10 {lab=VSS}
N 350 -10 400 -10 {lab=VSS}
N 400 -80 400 -50 {lab=VSS}
N 350 -80 400 -80 {lab=VSS}
C {code_shown.sym} -2180 -800 0 0 {name=NGSPICE1 only_toplevel=false value="
.lib /foss/pdks/sky130A/libs.tech/ngspice/sky130.lib.spice tt
.param vcm = 0.9
**Setup
Vdd vdd 0 1.8
Ven en 0 1.8
Ibias Vdd Ibias 5u
*Vdd vdd 0 SIN(1.8 0.1 600k)
Vss vss 0 0

*Uncomment sources below depending* 
*on what simulation needs to be run*
*AC simulation or (DC + Transient)*

*This line is not really needed -> Vdiff vdiff 0 0

*Transient + DC Transfer*
*Vdiff vdiff 0 SIN(0 0.001 10k)
*Bvp vp 0 V = vcm + V(vdiff)/2
*Bvn vn 0 V = vcm - V(vdiff)/2

*AC small signal*
Vp vp 0 vcm AC
Vn vn 0 vcm AC -1

**Simulation
.option temp=27 gmin=1e-12
.save all
.options savecurrents
.control
** Define input signal
let fsig = 10k
let tper = 1/fsig
** Define transient params
let tstop = 10*tper
let tstep = 0.001*tper

op
remzerovec
write miller_op_amp_rev9_layout_driven.raw
echo ---xm2---
let gds2 = @m.xm2.msky130_fd_pr__nfet_01v8_lvt[gds]
let ro2 = 1/gds2
echo ---xm4---
let gds4 = @m.xm4.msky130_fd_pr__pfet_01v8[gds]
let ro4 = 1/gds4
let RoD = 1/((1/ro2) + (1/ro4))
echo ---xm6---
print @m.xm6.msky130_fd_pr__nfet_01v8_lvt[vdsat]
echo -----COMMON SOURCE-----
echo ---xm7---
let gds7 = @m.xm7.msky130_fd_pr__pfet_01v8[gds]
let gm7 = @m.xm7.msky130_fd_pr__pfet_01v8[gm]
let r_zero = 1/gm7
print r_zero
let ro7 = 1/gds7
echo ---xm8---
let gds8 = @m.xm8.msky130_fd_pr__nfet_01v8_lvt[gds]
let ro8 = 1/gds8
echo ---xm10---
let gds10 = @m.xm10.msky130_fd_pr__nfet_01v8_lvt[gds]
let ro10 = 1/gds10
let Ros = 1/((1/ro7) + (1/(ro8+ro10)))


tran $&tstep $&tstop
let current = -i(vdd)
plot vp vn vout1
plot vp vn vout

dc vdiff -0.9 0.9 10m
let vin = vp -vn
plot vin vout1 vdd
meas dc vout1_at_zero find vout1 when vdiff=0

dc vdiff -0.9 0.9 10m
let vin = vp -vn
plot vin vout vdd
meas dc vout_at_zero find vout when vdiff=0

ac dec 200 1 10000Meg
let vin = vp - vn
let gain = db(vout/vin)
plot gain
meas ac gain_max MAX gain
let db_3 = gain_max - 3
print db_3
meas ac f_pole WHEN gain = db_3
meas ac f_u WHEN gain = 0
meas ac gain_10k FIND gain AT=10e3
let phase_deg = 180*cph(vout/vin)/pi
plot phase_deg
meas ac phase_at_fu FIND phase_deg AT=f_u
let phase_margin = 180 + phase_at_fu
print phase_margin
let gbw = 10^(gain_max/20) * f_pole
print gbw
setplot op1
print @m.xm2.msky130_fd_pr__nfet_01v8_lvt[vth]
print @m.xm2.msky130_fd_pr__nfet_01v8_lvt[gm]
print @m.xm2.msky130_fd_pr__nfet_01v8_lvt[vdsat]
print @m.xm7.msky130_fd_pr__pfet_01v8[vth]
print @m.xm7.msky130_fd_pr__pfet_01v8[gm]
print @m.xm7.msky130_fd_pr__pfet_01v8[vdsat]
print ro2
print ro4
print RoD
print ro10
print ro8
print ro8+ro10
print ro7
print Ros
let ro5 = 1/@m.xm5.msky130_fd_pr__nfet_01v8_lvt[gds]
print ro5
let Av1 = @m.xm2.msky130_fd_pr__nfet_01v8_lvt[gm] * RoD
let Av2 = @m.xm7.msky130_fd_pr__pfet_01v8[gm] * Ros
print Av1
print Av2
let x7_gm_id = @m.xm7.msky130_fd_pr__pfet_01v8[gm]/@m.xm7.msky130_fd_pr__pfet_01v8[id]
print x7_gm_id
let x4_gm_id = @m.xm4.msky130_fd_pr__pfet_01v8[gm]/@m.xm4.msky130_fd_pr__pfet_01v8[id]
print x4_gm_id
let x2_gm_id = @m.xm2.msky130_fd_pr__nfet_01v8_lvt[gm]/@m.xm2.msky130_fd_pr__nfet_01v8_lvt[id]
print x2_gm_id
.endc
"}
C {iopin.sym} 730 1960 1 0 {name=p4 lab=VSS}
C {lab_wire.sym} -890 -300 0 0 {name=p7 sig_type=std_logic lab=VN}
C {lab_wire.sym} -560 -750 0 0 {name=p8 sig_type=std_logic lab=Vpo}
C {lab_wire.sym} 440 40 0 0 {name=p9 sig_type=std_logic lab=VP}
C {devices/launcher.sym} -880 460 0 0 {name=h15
descr="Annotate OP" 
tclcommand="set show_hidden_texts 1; xschem annotate_op"
}
C {lab_wire.sym} -250 -810 0 0 {name=p10 sig_type=std_logic lab=Vout1}
C {lab_wire.sym} -760 60 0 0 {name=p11 sig_type=std_logic lab=Vz}
C {iopin.sym} 580 -1940 3 0 {name=p3 lab=VDD}
C {iopin.sym} -1290 250 3 0 {name=p6 lab=IBIAS}
C {opin.sym} 150 -720 0 0 {name=p13 lab=VOUT}
C {lab_wire.sym} -30 -720 0 0 {name=p21 sig_type=std_logic lab=VOUT}
C {iopin.sym} -820 720 2 0 {name=p5 lab=EN}
C {iopin.sym} -920 -300 2 0 {name=p12 lab=VN}
C {iopin.sym} 450 40 0 0 {name=p1 lab=VP}
C {lab_wire.sym} -740 -200 2 1 {name=p18 sig_type=std_logic lab=VSS}
C {lab_wire.sym} -310 -770 0 0 {name=p14 sig_type=std_logic lab=VSS}
C {sky130_fd_pr/cap_mim_m3_1.sym} -250 -680 0 0 {name=C2 model=cap_mim_m3_1 W=16.2 L=16.2 MF=1 spiceprefix=X}
C {sky130_fd_pr/nfet_01v8_lvt.sym} -820 950 3 1 {name=M5
W=7
L=1
nf=1
mult=1
ad="expr('int((@nf + 1)/2) * @W / @nf * 0.29')"
pd="expr('2*int((@nf + 1)/2) * (@W / @nf + 0.29)')"
as="expr('int((@nf + 2)/2) * @W / @nf * 0.29')"
ps="expr('2*int((@nf + 2)/2) * (@W / @nf + 0.29)')"
nrd="expr('0.29 / @W ')" nrs="expr('0.29 / @W ')"
sa=0 sb=0 sd=0
model=nfet_01v8_lvt
spiceprefix=X
}
C {sky130_fd_pr/nfet_01v8_lvt.sym} -730 950 1 0 {name=M6
W=7
L=1
nf=1
mult=1
ad="expr('int((@nf + 1)/2) * @W / @nf * 0.29')"
pd="expr('2*int((@nf + 1)/2) * (@W / @nf + 0.29)')"
as="expr('int((@nf + 2)/2) * @W / @nf * 0.29')"
ps="expr('2*int((@nf + 2)/2) * (@W / @nf + 0.29)')"
nrd="expr('0.29 / @W ')" nrs="expr('0.29 / @W ')"
sa=0 sb=0 sd=0
model=nfet_01v8_lvt
spiceprefix=X
}
C {sky130_fd_pr/nfet_01v8_lvt.sym} -640 950 3 1 {name=M8
W=7
L=1
nf=1
mult=1
ad="expr('int((@nf + 1)/2) * @W / @nf * 0.29')"
pd="expr('2*int((@nf + 1)/2) * (@W / @nf + 0.29)')"
as="expr('int((@nf + 2)/2) * @W / @nf * 0.29')"
ps="expr('2*int((@nf + 2)/2) * (@W / @nf + 0.29)')"
nrd="expr('0.29 / @W ')" nrs="expr('0.29 / @W ')"
sa=0 sb=0 sd=0
model=nfet_01v8_lvt
spiceprefix=X
}
C {sky130_fd_pr/nfet_01v8_lvt.sym} -530 950 3 1 {name=M9
W=7
L=1
nf=1
mult=1
ad="expr('int((@nf + 1)/2) * @W / @nf * 0.29')"
pd="expr('2*int((@nf + 1)/2) * (@W / @nf + 0.29)')"
as="expr('int((@nf + 2)/2) * @W / @nf * 0.29')"
ps="expr('2*int((@nf + 2)/2) * (@W / @nf + 0.29)')"
nrd="expr('0.29 / @W ')" nrs="expr('0.29 / @W ')"
sa=0 sb=0 sd=0
model=nfet_01v8_lvt
spiceprefix=X
}
C {sky130_fd_pr/nfet_01v8_lvt.sym} -440 950 3 1 {name=M10
W=7
L=1
nf=1
mult=1
ad="expr('int((@nf + 1)/2) * @W / @nf * 0.29')"
pd="expr('2*int((@nf + 1)/2) * (@W / @nf + 0.29)')"
as="expr('int((@nf + 2)/2) * @W / @nf * 0.29')"
ps="expr('2*int((@nf + 2)/2) * (@W / @nf + 0.29)')"
nrd="expr('0.29 / @W ')" nrs="expr('0.29 / @W ')"
sa=0 sb=0 sd=0
model=nfet_01v8_lvt
spiceprefix=X
}
C {sky130_fd_pr/nfet_01v8_lvt.sym} -350 950 3 1 {name=M11
W=7
L=1
nf=1
mult=1
ad="expr('int((@nf + 1)/2) * @W / @nf * 0.29')"
pd="expr('2*int((@nf + 1)/2) * (@W / @nf + 0.29)')"
as="expr('int((@nf + 2)/2) * @W / @nf * 0.29')"
ps="expr('2*int((@nf + 2)/2) * (@W / @nf + 0.29)')"
nrd="expr('0.29 / @W ')" nrs="expr('0.29 / @W ')"
sa=0 sb=0 sd=0
model=nfet_01v8_lvt
spiceprefix=X
}
C {sky130_fd_pr/nfet_01v8_lvt.sym} -160 950 3 1 {name=M13
W=7
L=1
nf=1
mult=1
ad="expr('int((@nf + 1)/2) * @W / @nf * 0.29')"
pd="expr('2*int((@nf + 1)/2) * (@W / @nf + 0.29)')"
as="expr('int((@nf + 2)/2) * @W / @nf * 0.29')"
ps="expr('2*int((@nf + 2)/2) * (@W / @nf + 0.29)')"
nrd="expr('0.29 / @W ')" nrs="expr('0.29 / @W ')"
sa=0 sb=0 sd=0
model=nfet_01v8_lvt
spiceprefix=X
}
C {sky130_fd_pr/nfet_01v8_lvt.sym} -240 950 1 0 {name=M14
W=7
L=1
nf=1
mult=1
ad="expr('int((@nf + 1)/2) * @W / @nf * 0.29')"
pd="expr('2*int((@nf + 1)/2) * (@W / @nf + 0.29)')"
as="expr('int((@nf + 2)/2) * @W / @nf * 0.29')"
ps="expr('2*int((@nf + 2)/2) * (@W / @nf + 0.29)')"
nrd="expr('0.29 / @W ')" nrs="expr('0.29 / @W ')"
sa=0 sb=0 sd=0
model=nfet_01v8_lvt
spiceprefix=X
}
C {sky130_fd_pr/nfet_01v8_lvt.sym} -70 950 3 1 {name=M15
W=7
L=1
nf=1
mult=1
ad="expr('int((@nf + 1)/2) * @W / @nf * 0.29')"
pd="expr('2*int((@nf + 1)/2) * (@W / @nf + 0.29)')"
as="expr('int((@nf + 2)/2) * @W / @nf * 0.29')"
ps="expr('2*int((@nf + 2)/2) * (@W / @nf + 0.29)')"
nrd="expr('0.29 / @W ')" nrs="expr('0.29 / @W ')"
sa=0 sb=0 sd=0
model=nfet_01v8_lvt
spiceprefix=X
}
C {sky130_fd_pr/nfet_01v8_lvt.sym} -120 1300 1 0 {name=M16
W=3
L=1
nf=1
mult=1
ad="expr('int((@nf + 1)/2) * @W / @nf * 0.29')"
pd="expr('2*int((@nf + 1)/2) * (@W / @nf + 0.29)')"
as="expr('int((@nf + 2)/2) * @W / @nf * 0.29')"
ps="expr('2*int((@nf + 2)/2) * (@W / @nf + 0.29)')"
nrd="expr('0.29 / @W ')" nrs="expr('0.29 / @W ')"
sa=0 sb=0 sd=0
model=nfet_01v8_lvt
spiceprefix=X
}
C {sky130_fd_pr/nfet_01v8_lvt.sym} -30 1300 3 1 {name=M17
W=3
L=1
nf=1
mult=1
ad="expr('int((@nf + 1)/2) * @W / @nf * 0.29')"
pd="expr('2*int((@nf + 1)/2) * (@W / @nf + 0.29)')"
as="expr('int((@nf + 2)/2) * @W / @nf * 0.29')"
ps="expr('2*int((@nf + 2)/2) * (@W / @nf + 0.29)')"
nrd="expr('0.29 / @W ')" nrs="expr('0.29 / @W ')"
sa=0 sb=0 sd=0
model=nfet_01v8_lvt
spiceprefix=X
}
C {sky130_fd_pr/nfet_01v8_lvt.sym} -230 1300 3 1 {name=M18
W=3
L=1
nf=1
mult=1
ad="expr('int((@nf + 1)/2) * @W / @nf * 0.29')"
pd="expr('2*int((@nf + 1)/2) * (@W / @nf + 0.29)')"
as="expr('int((@nf + 2)/2) * @W / @nf * 0.29')"
ps="expr('2*int((@nf + 2)/2) * (@W / @nf + 0.29)')"
nrd="expr('0.29 / @W ')" nrs="expr('0.29 / @W ')"
sa=0 sb=0 sd=0
model=nfet_01v8_lvt
spiceprefix=X
}
C {sky130_fd_pr/nfet_01v8_lvt.sym} -310 1300 1 0 {name=M19
W=3
L=1
nf=1
mult=1
ad="expr('int((@nf + 1)/2) * @W / @nf * 0.29')"
pd="expr('2*int((@nf + 1)/2) * (@W / @nf + 0.29)')"
as="expr('int((@nf + 2)/2) * @W / @nf * 0.29')"
ps="expr('2*int((@nf + 2)/2) * (@W / @nf + 0.29)')"
nrd="expr('0.29 / @W ')" nrs="expr('0.29 / @W ')"
sa=0 sb=0 sd=0
model=nfet_01v8_lvt
spiceprefix=X
}
C {sky130_fd_pr/nfet_01v8_lvt.sym} -390 1300 3 1 {name=M20
W=3
L=1
nf=1
mult=1
ad="expr('int((@nf + 1)/2) * @W / @nf * 0.29')"
pd="expr('2*int((@nf + 1)/2) * (@W / @nf + 0.29)')"
as="expr('int((@nf + 2)/2) * @W / @nf * 0.29')"
ps="expr('2*int((@nf + 2)/2) * (@W / @nf + 0.29)')"
nrd="expr('0.29 / @W ')" nrs="expr('0.29 / @W ')"
sa=0 sb=0 sd=0
model=nfet_01v8_lvt
spiceprefix=X
}
C {sky130_fd_pr/nfet_01v8_lvt.sym} -470 1300 1 0 {name=M21
W=3
L=1
nf=1
mult=1
ad="expr('int((@nf + 1)/2) * @W / @nf * 0.29')"
pd="expr('2*int((@nf + 1)/2) * (@W / @nf + 0.29)')"
as="expr('int((@nf + 2)/2) * @W / @nf * 0.29')"
ps="expr('2*int((@nf + 2)/2) * (@W / @nf + 0.29)')"
nrd="expr('0.29 / @W ')" nrs="expr('0.29 / @W ')"
sa=0 sb=0 sd=0
model=nfet_01v8_lvt
spiceprefix=X
}
C {sky130_fd_pr/nfet_01v8_lvt.sym} -550 1300 3 1 {name=M22
W=3
L=1
nf=1
mult=1
ad="expr('int((@nf + 1)/2) * @W / @nf * 0.29')"
pd="expr('2*int((@nf + 1)/2) * (@W / @nf + 0.29)')"
as="expr('int((@nf + 2)/2) * @W / @nf * 0.29')"
ps="expr('2*int((@nf + 2)/2) * (@W / @nf + 0.29)')"
nrd="expr('0.29 / @W ')" nrs="expr('0.29 / @W ')"
sa=0 sb=0 sd=0
model=nfet_01v8_lvt
spiceprefix=X
}
C {sky130_fd_pr/nfet_01v8_lvt.sym} -640 1300 1 0 {name=M23
W=3
L=1
nf=1
mult=1
ad="expr('int((@nf + 1)/2) * @W / @nf * 0.29')"
pd="expr('2*int((@nf + 1)/2) * (@W / @nf + 0.29)')"
as="expr('int((@nf + 2)/2) * @W / @nf * 0.29')"
ps="expr('2*int((@nf + 2)/2) * (@W / @nf + 0.29)')"
nrd="expr('0.29 / @W ')" nrs="expr('0.29 / @W ')"
sa=0 sb=0 sd=0
model=nfet_01v8_lvt
spiceprefix=X
}
C {sky130_fd_pr/nfet_01v8_lvt.sym} 70 1300 1 0 {name=M24
W=3
L=1
nf=1
mult=1
ad="expr('int((@nf + 1)/2) * @W / @nf * 0.29')"
pd="expr('2*int((@nf + 1)/2) * (@W / @nf + 0.29)')"
as="expr('int((@nf + 2)/2) * @W / @nf * 0.29')"
ps="expr('2*int((@nf + 2)/2) * (@W / @nf + 0.29)')"
nrd="expr('0.29 / @W ')" nrs="expr('0.29 / @W ')"
sa=0 sb=0 sd=0
model=nfet_01v8_lvt
spiceprefix=X
}
C {sky130_fd_pr/nfet_01v8_lvt.sym} 150 1300 3 1 {name=M25
W=3
L=1
nf=1
mult=1
ad="expr('int((@nf + 1)/2) * @W / @nf * 0.29')"
pd="expr('2*int((@nf + 1)/2) * (@W / @nf + 0.29)')"
as="expr('int((@nf + 2)/2) * @W / @nf * 0.29')"
ps="expr('2*int((@nf + 2)/2) * (@W / @nf + 0.29)')"
nrd="expr('0.29 / @W ')" nrs="expr('0.29 / @W ')"
sa=0 sb=0 sd=0
model=nfet_01v8_lvt
spiceprefix=X
}
C {sky130_fd_pr/nfet_01v8_lvt.sym} 230 1300 1 0 {name=M26
W=3
L=1
nf=1
mult=1
ad="expr('int((@nf + 1)/2) * @W / @nf * 0.29')"
pd="expr('2*int((@nf + 1)/2) * (@W / @nf + 0.29)')"
as="expr('int((@nf + 2)/2) * @W / @nf * 0.29')"
ps="expr('2*int((@nf + 2)/2) * (@W / @nf + 0.29)')"
nrd="expr('0.29 / @W ')" nrs="expr('0.29 / @W ')"
sa=0 sb=0 sd=0
model=nfet_01v8_lvt
spiceprefix=X
}
C {sky130_fd_pr/nfet_01v8_lvt.sym} 310 1300 3 1 {name=M27
W=3
L=1
nf=1
mult=1
ad="expr('int((@nf + 1)/2) * @W / @nf * 0.29')"
pd="expr('2*int((@nf + 1)/2) * (@W / @nf + 0.29)')"
as="expr('int((@nf + 2)/2) * @W / @nf * 0.29')"
ps="expr('2*int((@nf + 2)/2) * (@W / @nf + 0.29)')"
nrd="expr('0.29 / @W ')" nrs="expr('0.29 / @W ')"
sa=0 sb=0 sd=0
model=nfet_01v8_lvt
spiceprefix=X
}
C {sky130_fd_pr/nfet_01v8_lvt.sym} 390 1300 1 0 {name=M28
W=3
L=1
nf=1
mult=1
ad="expr('int((@nf + 1)/2) * @W / @nf * 0.29')"
pd="expr('2*int((@nf + 1)/2) * (@W / @nf + 0.29)')"
as="expr('int((@nf + 2)/2) * @W / @nf * 0.29')"
ps="expr('2*int((@nf + 2)/2) * (@W / @nf + 0.29)')"
nrd="expr('0.29 / @W ')" nrs="expr('0.29 / @W ')"
sa=0 sb=0 sd=0
model=nfet_01v8_lvt
spiceprefix=X
}
C {sky130_fd_pr/nfet_01v8_lvt.sym} 480 1300 3 1 {name=M29
W=3
L=1
nf=1
mult=1
ad="expr('int((@nf + 1)/2) * @W / @nf * 0.29')"
pd="expr('2*int((@nf + 1)/2) * (@W / @nf + 0.29)')"
as="expr('int((@nf + 2)/2) * @W / @nf * 0.29')"
ps="expr('2*int((@nf + 2)/2) * (@W / @nf + 0.29)')"
nrd="expr('0.29 / @W ')" nrs="expr('0.29 / @W ')"
sa=0 sb=0 sd=0
model=nfet_01v8_lvt
spiceprefix=X
}
C {sky130_fd_pr/nfet_01v8_lvt.sym} -720 1300 3 1 {name=M30
W=3
L=1
nf=1
mult=1
ad="expr('int((@nf + 1)/2) * @W / @nf * 0.29')"
pd="expr('2*int((@nf + 1)/2) * (@W / @nf + 0.29)')"
as="expr('int((@nf + 2)/2) * @W / @nf * 0.29')"
ps="expr('2*int((@nf + 2)/2) * (@W / @nf + 0.29)')"
nrd="expr('0.29 / @W ')" nrs="expr('0.29 / @W ')"
sa=0 sb=0 sd=0
model=nfet_01v8_lvt
spiceprefix=X
}
C {sky130_fd_pr/nfet_01v8_lvt.sym} 560 1300 1 0 {name=M31
W=3
L=1
nf=1
mult=1
ad="expr('int((@nf + 1)/2) * @W / @nf * 0.29')"
pd="expr('2*int((@nf + 1)/2) * (@W / @nf + 0.29)')"
as="expr('int((@nf + 2)/2) * @W / @nf * 0.29')"
ps="expr('2*int((@nf + 2)/2) * (@W / @nf + 0.29)')"
nrd="expr('0.29 / @W ')" nrs="expr('0.29 / @W ')"
sa=0 sb=0 sd=0
model=nfet_01v8_lvt
spiceprefix=X
}
C {sky130_fd_pr/nfet_01v8_lvt.sym} -130 1160 3 0 {name=M32
W=3
L=1
nf=1
mult=1
ad="expr('int((@nf + 1)/2) * @W / @nf * 0.29')"
pd="expr('2*int((@nf + 1)/2) * (@W / @nf + 0.29)')"
as="expr('int((@nf + 2)/2) * @W / @nf * 0.29')"
ps="expr('2*int((@nf + 2)/2) * (@W / @nf + 0.29)')"
nrd="expr('0.29 / @W ')" nrs="expr('0.29 / @W ')"
sa=0 sb=0 sd=0
model=nfet_01v8_lvt
spiceprefix=X
}
C {sky130_fd_pr/nfet_01v8_lvt.sym} -210 1160 1 1 {name=M33
W=3
L=1
nf=1
mult=1
ad="expr('int((@nf + 1)/2) * @W / @nf * 0.29')"
pd="expr('2*int((@nf + 1)/2) * (@W / @nf + 0.29)')"
as="expr('int((@nf + 2)/2) * @W / @nf * 0.29')"
ps="expr('2*int((@nf + 2)/2) * (@W / @nf + 0.29)')"
nrd="expr('0.29 / @W ')" nrs="expr('0.29 / @W ')"
sa=0 sb=0 sd=0
model=nfet_01v8_lvt
spiceprefix=X
}
C {sky130_fd_pr/nfet_01v8_lvt.sym} -290 1160 3 0 {name=M34
W=3
L=1
nf=1
mult=1
ad="expr('int((@nf + 1)/2) * @W / @nf * 0.29')"
pd="expr('2*int((@nf + 1)/2) * (@W / @nf + 0.29)')"
as="expr('int((@nf + 2)/2) * @W / @nf * 0.29')"
ps="expr('2*int((@nf + 2)/2) * (@W / @nf + 0.29)')"
nrd="expr('0.29 / @W ')" nrs="expr('0.29 / @W ')"
sa=0 sb=0 sd=0
model=nfet_01v8_lvt
spiceprefix=X
}
C {sky130_fd_pr/nfet_01v8_lvt.sym} -370 1160 1 1 {name=M35
W=3
L=1
nf=1
mult=1
ad="expr('int((@nf + 1)/2) * @W / @nf * 0.29')"
pd="expr('2*int((@nf + 1)/2) * (@W / @nf + 0.29)')"
as="expr('int((@nf + 2)/2) * @W / @nf * 0.29')"
ps="expr('2*int((@nf + 2)/2) * (@W / @nf + 0.29)')"
nrd="expr('0.29 / @W ')" nrs="expr('0.29 / @W ')"
sa=0 sb=0 sd=0
model=nfet_01v8_lvt
spiceprefix=X
}
C {sky130_fd_pr/nfet_01v8_lvt.sym} -450 1160 3 0 {name=M36
W=3
L=1
nf=1
mult=1
ad="expr('int((@nf + 1)/2) * @W / @nf * 0.29')"
pd="expr('2*int((@nf + 1)/2) * (@W / @nf + 0.29)')"
as="expr('int((@nf + 2)/2) * @W / @nf * 0.29')"
ps="expr('2*int((@nf + 2)/2) * (@W / @nf + 0.29)')"
nrd="expr('0.29 / @W ')" nrs="expr('0.29 / @W ')"
sa=0 sb=0 sd=0
model=nfet_01v8_lvt
spiceprefix=X
}
C {sky130_fd_pr/nfet_01v8_lvt.sym} -540 1160 1 1 {name=M37
W=3
L=1
nf=1
mult=1
ad="expr('int((@nf + 1)/2) * @W / @nf * 0.29')"
pd="expr('2*int((@nf + 1)/2) * (@W / @nf + 0.29)')"
as="expr('int((@nf + 2)/2) * @W / @nf * 0.29')"
ps="expr('2*int((@nf + 2)/2) * (@W / @nf + 0.29)')"
nrd="expr('0.29 / @W ')" nrs="expr('0.29 / @W ')"
sa=0 sb=0 sd=0
model=nfet_01v8_lvt
spiceprefix=X
}
C {sky130_fd_pr/nfet_01v8_lvt.sym} -30 1160 1 1 {name=M38
W=3
L=1
nf=1
mult=1
ad="expr('int((@nf + 1)/2) * @W / @nf * 0.29')"
pd="expr('2*int((@nf + 1)/2) * (@W / @nf + 0.29)')"
as="expr('int((@nf + 2)/2) * @W / @nf * 0.29')"
ps="expr('2*int((@nf + 2)/2) * (@W / @nf + 0.29)')"
nrd="expr('0.29 / @W ')" nrs="expr('0.29 / @W ')"
sa=0 sb=0 sd=0
model=nfet_01v8_lvt
spiceprefix=X
}
C {sky130_fd_pr/nfet_01v8_lvt.sym} 50 1160 3 0 {name=M39
W=3
L=1
nf=1
mult=1
ad="expr('int((@nf + 1)/2) * @W / @nf * 0.29')"
pd="expr('2*int((@nf + 1)/2) * (@W / @nf + 0.29)')"
as="expr('int((@nf + 2)/2) * @W / @nf * 0.29')"
ps="expr('2*int((@nf + 2)/2) * (@W / @nf + 0.29)')"
nrd="expr('0.29 / @W ')" nrs="expr('0.29 / @W ')"
sa=0 sb=0 sd=0
model=nfet_01v8_lvt
spiceprefix=X
}
C {sky130_fd_pr/nfet_01v8_lvt.sym} 130 1160 1 1 {name=M40
W=3
L=1
nf=1
mult=1
ad="expr('int((@nf + 1)/2) * @W / @nf * 0.29')"
pd="expr('2*int((@nf + 1)/2) * (@W / @nf + 0.29)')"
as="expr('int((@nf + 2)/2) * @W / @nf * 0.29')"
ps="expr('2*int((@nf + 2)/2) * (@W / @nf + 0.29)')"
nrd="expr('0.29 / @W ')" nrs="expr('0.29 / @W ')"
sa=0 sb=0 sd=0
model=nfet_01v8_lvt
spiceprefix=X
}
C {sky130_fd_pr/nfet_01v8_lvt.sym} 210 1160 3 0 {name=M41
W=3
L=1
nf=1
mult=1
ad="expr('int((@nf + 1)/2) * @W / @nf * 0.29')"
pd="expr('2*int((@nf + 1)/2) * (@W / @nf + 0.29)')"
as="expr('int((@nf + 2)/2) * @W / @nf * 0.29')"
ps="expr('2*int((@nf + 2)/2) * (@W / @nf + 0.29)')"
nrd="expr('0.29 / @W ')" nrs="expr('0.29 / @W ')"
sa=0 sb=0 sd=0
model=nfet_01v8_lvt
spiceprefix=X
}
C {sky130_fd_pr/nfet_01v8_lvt.sym} 290 1160 1 1 {name=M42
W=3
L=1
nf=1
mult=1
ad="expr('int((@nf + 1)/2) * @W / @nf * 0.29')"
pd="expr('2*int((@nf + 1)/2) * (@W / @nf + 0.29)')"
as="expr('int((@nf + 2)/2) * @W / @nf * 0.29')"
ps="expr('2*int((@nf + 2)/2) * (@W / @nf + 0.29)')"
nrd="expr('0.29 / @W ')" nrs="expr('0.29 / @W ')"
sa=0 sb=0 sd=0
model=nfet_01v8_lvt
spiceprefix=X
}
C {sky130_fd_pr/nfet_01v8_lvt.sym} 380 1160 3 0 {name=M43
W=3
L=1
nf=1
mult=1
ad="expr('int((@nf + 1)/2) * @W / @nf * 0.29')"
pd="expr('2*int((@nf + 1)/2) * (@W / @nf + 0.29)')"
as="expr('int((@nf + 2)/2) * @W / @nf * 0.29')"
ps="expr('2*int((@nf + 2)/2) * (@W / @nf + 0.29)')"
nrd="expr('0.29 / @W ')" nrs="expr('0.29 / @W ')"
sa=0 sb=0 sd=0
model=nfet_01v8_lvt
spiceprefix=X
}
C {sky130_fd_pr/nfet_01v8_lvt.sym} 460 1160 1 1 {name=M44
W=3
L=1
nf=1
mult=1
ad="expr('int((@nf + 1)/2) * @W / @nf * 0.29')"
pd="expr('2*int((@nf + 1)/2) * (@W / @nf + 0.29)')"
as="expr('int((@nf + 2)/2) * @W / @nf * 0.29')"
ps="expr('2*int((@nf + 2)/2) * (@W / @nf + 0.29)')"
nrd="expr('0.29 / @W ')" nrs="expr('0.29 / @W ')"
sa=0 sb=0 sd=0
model=nfet_01v8_lvt
spiceprefix=X
}
C {sky130_fd_pr/nfet_01v8_lvt.sym} -630 1160 3 0 {name=M45
W=3
L=1
nf=1
mult=1
ad="expr('int((@nf + 1)/2) * @W / @nf * 0.29')"
pd="expr('2*int((@nf + 1)/2) * (@W / @nf + 0.29)')"
as="expr('int((@nf + 2)/2) * @W / @nf * 0.29')"
ps="expr('2*int((@nf + 2)/2) * (@W / @nf + 0.29)')"
nrd="expr('0.29 / @W ')" nrs="expr('0.29 / @W ')"
sa=0 sb=0 sd=0
model=nfet_01v8_lvt
spiceprefix=X
}
C {sky130_fd_pr/nfet_01v8_lvt.sym} -720 1160 3 0 {name=M46
W=3
L=1
nf=1
mult=1
ad="expr('int((@nf + 1)/2) * @W / @nf * 0.29')"
pd="expr('2*int((@nf + 1)/2) * (@W / @nf + 0.29)')"
as="expr('int((@nf + 2)/2) * @W / @nf * 0.29')"
ps="expr('2*int((@nf + 2)/2) * (@W / @nf + 0.29)')"
nrd="expr('0.29 / @W ')" nrs="expr('0.29 / @W ')"
sa=0 sb=0 sd=0
model=nfet_01v8_lvt
spiceprefix=X
}
C {sky130_fd_pr/nfet_01v8_lvt.sym} 540 1160 1 1 {name=M47
W=3
L=1
nf=1
mult=1
ad="expr('int((@nf + 1)/2) * @W / @nf * 0.29')"
pd="expr('2*int((@nf + 1)/2) * (@W / @nf + 0.29)')"
as="expr('int((@nf + 2)/2) * @W / @nf * 0.29')"
ps="expr('2*int((@nf + 2)/2) * (@W / @nf + 0.29)')"
nrd="expr('0.29 / @W ')" nrs="expr('0.29 / @W ')"
sa=0 sb=0 sd=0
model=nfet_01v8_lvt
spiceprefix=X
}
C {sky130_fd_pr/nfet_01v8_lvt.sym} -130 1440 3 1 {name=M48
W=3
L=1
nf=1
mult=1
ad="expr('int((@nf + 1)/2) * @W / @nf * 0.29')"
pd="expr('2*int((@nf + 1)/2) * (@W / @nf + 0.29)')"
as="expr('int((@nf + 2)/2) * @W / @nf * 0.29')"
ps="expr('2*int((@nf + 2)/2) * (@W / @nf + 0.29)')"
nrd="expr('0.29 / @W ')" nrs="expr('0.29 / @W ')"
sa=0 sb=0 sd=0
model=nfet_01v8_lvt
spiceprefix=X
}
C {sky130_fd_pr/nfet_01v8_lvt.sym} -210 1440 1 0 {name=M49
W=3
L=1
nf=1
mult=1
ad="expr('int((@nf + 1)/2) * @W / @nf * 0.29')"
pd="expr('2*int((@nf + 1)/2) * (@W / @nf + 0.29)')"
as="expr('int((@nf + 2)/2) * @W / @nf * 0.29')"
ps="expr('2*int((@nf + 2)/2) * (@W / @nf + 0.29)')"
nrd="expr('0.29 / @W ')" nrs="expr('0.29 / @W ')"
sa=0 sb=0 sd=0
model=nfet_01v8_lvt
spiceprefix=X
}
C {sky130_fd_pr/nfet_01v8_lvt.sym} -290 1440 3 1 {name=M50
W=3
L=1
nf=1
mult=1
ad="expr('int((@nf + 1)/2) * @W / @nf * 0.29')"
pd="expr('2*int((@nf + 1)/2) * (@W / @nf + 0.29)')"
as="expr('int((@nf + 2)/2) * @W / @nf * 0.29')"
ps="expr('2*int((@nf + 2)/2) * (@W / @nf + 0.29)')"
nrd="expr('0.29 / @W ')" nrs="expr('0.29 / @W ')"
sa=0 sb=0 sd=0
model=nfet_01v8_lvt
spiceprefix=X
}
C {sky130_fd_pr/nfet_01v8_lvt.sym} -370 1440 1 0 {name=M51
W=3
L=1
nf=1
mult=1
ad="expr('int((@nf + 1)/2) * @W / @nf * 0.29')"
pd="expr('2*int((@nf + 1)/2) * (@W / @nf + 0.29)')"
as="expr('int((@nf + 2)/2) * @W / @nf * 0.29')"
ps="expr('2*int((@nf + 2)/2) * (@W / @nf + 0.29)')"
nrd="expr('0.29 / @W ')" nrs="expr('0.29 / @W ')"
sa=0 sb=0 sd=0
model=nfet_01v8_lvt
spiceprefix=X
}
C {sky130_fd_pr/nfet_01v8_lvt.sym} -450 1440 3 1 {name=M52
W=3
L=1
nf=1
mult=1
ad="expr('int((@nf + 1)/2) * @W / @nf * 0.29')"
pd="expr('2*int((@nf + 1)/2) * (@W / @nf + 0.29)')"
as="expr('int((@nf + 2)/2) * @W / @nf * 0.29')"
ps="expr('2*int((@nf + 2)/2) * (@W / @nf + 0.29)')"
nrd="expr('0.29 / @W ')" nrs="expr('0.29 / @W ')"
sa=0 sb=0 sd=0
model=nfet_01v8_lvt
spiceprefix=X
}
C {sky130_fd_pr/nfet_01v8_lvt.sym} -540 1440 1 0 {name=M53
W=3
L=1
nf=1
mult=1
ad="expr('int((@nf + 1)/2) * @W / @nf * 0.29')"
pd="expr('2*int((@nf + 1)/2) * (@W / @nf + 0.29)')"
as="expr('int((@nf + 2)/2) * @W / @nf * 0.29')"
ps="expr('2*int((@nf + 2)/2) * (@W / @nf + 0.29)')"
nrd="expr('0.29 / @W ')" nrs="expr('0.29 / @W ')"
sa=0 sb=0 sd=0
model=nfet_01v8_lvt
spiceprefix=X
}
C {sky130_fd_pr/nfet_01v8_lvt.sym} -30 1440 1 0 {name=M54
W=3
L=1
nf=1
mult=1
ad="expr('int((@nf + 1)/2) * @W / @nf * 0.29')"
pd="expr('2*int((@nf + 1)/2) * (@W / @nf + 0.29)')"
as="expr('int((@nf + 2)/2) * @W / @nf * 0.29')"
ps="expr('2*int((@nf + 2)/2) * (@W / @nf + 0.29)')"
nrd="expr('0.29 / @W ')" nrs="expr('0.29 / @W ')"
sa=0 sb=0 sd=0
model=nfet_01v8_lvt
spiceprefix=X
}
C {sky130_fd_pr/nfet_01v8_lvt.sym} 50 1440 3 1 {name=M55
W=3
L=1
nf=1
mult=1
ad="expr('int((@nf + 1)/2) * @W / @nf * 0.29')"
pd="expr('2*int((@nf + 1)/2) * (@W / @nf + 0.29)')"
as="expr('int((@nf + 2)/2) * @W / @nf * 0.29')"
ps="expr('2*int((@nf + 2)/2) * (@W / @nf + 0.29)')"
nrd="expr('0.29 / @W ')" nrs="expr('0.29 / @W ')"
sa=0 sb=0 sd=0
model=nfet_01v8_lvt
spiceprefix=X
}
C {sky130_fd_pr/nfet_01v8_lvt.sym} 130 1440 1 0 {name=M56
W=3
L=1
nf=1
mult=1
ad="expr('int((@nf + 1)/2) * @W / @nf * 0.29')"
pd="expr('2*int((@nf + 1)/2) * (@W / @nf + 0.29)')"
as="expr('int((@nf + 2)/2) * @W / @nf * 0.29')"
ps="expr('2*int((@nf + 2)/2) * (@W / @nf + 0.29)')"
nrd="expr('0.29 / @W ')" nrs="expr('0.29 / @W ')"
sa=0 sb=0 sd=0
model=nfet_01v8_lvt
spiceprefix=X
}
C {sky130_fd_pr/nfet_01v8_lvt.sym} 210 1440 3 1 {name=M57
W=3
L=1
nf=1
mult=1
ad="expr('int((@nf + 1)/2) * @W / @nf * 0.29')"
pd="expr('2*int((@nf + 1)/2) * (@W / @nf + 0.29)')"
as="expr('int((@nf + 2)/2) * @W / @nf * 0.29')"
ps="expr('2*int((@nf + 2)/2) * (@W / @nf + 0.29)')"
nrd="expr('0.29 / @W ')" nrs="expr('0.29 / @W ')"
sa=0 sb=0 sd=0
model=nfet_01v8_lvt
spiceprefix=X
}
C {sky130_fd_pr/nfet_01v8_lvt.sym} 290 1440 1 0 {name=M58
W=3
L=1
nf=1
mult=1
ad="expr('int((@nf + 1)/2) * @W / @nf * 0.29')"
pd="expr('2*int((@nf + 1)/2) * (@W / @nf + 0.29)')"
as="expr('int((@nf + 2)/2) * @W / @nf * 0.29')"
ps="expr('2*int((@nf + 2)/2) * (@W / @nf + 0.29)')"
nrd="expr('0.29 / @W ')" nrs="expr('0.29 / @W ')"
sa=0 sb=0 sd=0
model=nfet_01v8_lvt
spiceprefix=X
}
C {sky130_fd_pr/nfet_01v8_lvt.sym} 380 1440 3 1 {name=M59
W=3
L=1
nf=1
mult=1
ad="expr('int((@nf + 1)/2) * @W / @nf * 0.29')"
pd="expr('2*int((@nf + 1)/2) * (@W / @nf + 0.29)')"
as="expr('int((@nf + 2)/2) * @W / @nf * 0.29')"
ps="expr('2*int((@nf + 2)/2) * (@W / @nf + 0.29)')"
nrd="expr('0.29 / @W ')" nrs="expr('0.29 / @W ')"
sa=0 sb=0 sd=0
model=nfet_01v8_lvt
spiceprefix=X
}
C {sky130_fd_pr/nfet_01v8_lvt.sym} 460 1440 1 0 {name=M60
W=3
L=1
nf=1
mult=1
ad="expr('int((@nf + 1)/2) * @W / @nf * 0.29')"
pd="expr('2*int((@nf + 1)/2) * (@W / @nf + 0.29)')"
as="expr('int((@nf + 2)/2) * @W / @nf * 0.29')"
ps="expr('2*int((@nf + 2)/2) * (@W / @nf + 0.29)')"
nrd="expr('0.29 / @W ')" nrs="expr('0.29 / @W ')"
sa=0 sb=0 sd=0
model=nfet_01v8_lvt
spiceprefix=X
}
C {sky130_fd_pr/nfet_01v8_lvt.sym} -630 1440 3 1 {name=M61
W=3
L=1
nf=1
mult=1
ad="expr('int((@nf + 1)/2) * @W / @nf * 0.29')"
pd="expr('2*int((@nf + 1)/2) * (@W / @nf + 0.29)')"
as="expr('int((@nf + 2)/2) * @W / @nf * 0.29')"
ps="expr('2*int((@nf + 2)/2) * (@W / @nf + 0.29)')"
nrd="expr('0.29 / @W ')" nrs="expr('0.29 / @W ')"
sa=0 sb=0 sd=0
model=nfet_01v8_lvt
spiceprefix=X
}
C {sky130_fd_pr/nfet_01v8_lvt.sym} -720 1440 3 1 {name=M62
W=3
L=1
nf=1
mult=1
ad="expr('int((@nf + 1)/2) * @W / @nf * 0.29')"
pd="expr('2*int((@nf + 1)/2) * (@W / @nf + 0.29)')"
as="expr('int((@nf + 2)/2) * @W / @nf * 0.29')"
ps="expr('2*int((@nf + 2)/2) * (@W / @nf + 0.29)')"
nrd="expr('0.29 / @W ')" nrs="expr('0.29 / @W ')"
sa=0 sb=0 sd=0
model=nfet_01v8_lvt
spiceprefix=X
}
C {sky130_fd_pr/nfet_01v8_lvt.sym} 540 1440 1 0 {name=M63
W=3
L=1
nf=1
mult=1
ad="expr('int((@nf + 1)/2) * @W / @nf * 0.29')"
pd="expr('2*int((@nf + 1)/2) * (@W / @nf + 0.29)')"
as="expr('int((@nf + 2)/2) * @W / @nf * 0.29')"
ps="expr('2*int((@nf + 2)/2) * (@W / @nf + 0.29)')"
nrd="expr('0.29 / @W ')" nrs="expr('0.29 / @W ')"
sa=0 sb=0 sd=0
model=nfet_01v8_lvt
spiceprefix=X
}
C {sky130_fd_pr/pfet_01v8.sym} -90 -1480 3 0 {name=M68
W=1
L=0.4
nf=1
mult=1
ad="'int((nf+1)/2) * W/nf * 0.29'" 
pd="'2*int((nf+1)/2) * (W/nf + 0.29)'"
as="'int((nf+2)/2) * W/nf * 0.29'" 
ps="'2*int((nf+2)/2) * (W/nf + 0.29)'"
nrd="'0.29 / W'" nrs="'0.29 / W'"
sa=0 sb=0 sd=0
model=pfet_01v8
spiceprefix=X
}
C {sky130_fd_pr/pfet_01v8.sym} -10 -1480 1 1 {name=M69
W=1
L=0.4
nf=1
mult=1
ad="'int((nf+1)/2) * W/nf * 0.29'" 
pd="'2*int((nf+1)/2) * (W/nf + 0.29)'"
as="'int((nf+2)/2) * W/nf * 0.29'" 
ps="'2*int((nf+2)/2) * (W/nf + 0.29)'"
nrd="'0.29 / W'" nrs="'0.29 / W'"
sa=0 sb=0 sd=0
model=pfet_01v8
spiceprefix=X
}
C {sky130_fd_pr/pfet_01v8.sym} 100 -1390 3 1 {name=M70
W=1
L=0.4
nf=1
mult=1
ad="'int((nf+1)/2) * W/nf * 0.29'" 
pd="'2*int((nf+1)/2) * (W/nf + 0.29)'"
as="'int((nf+2)/2) * W/nf * 0.29'" 
ps="'2*int((nf+2)/2) * (W/nf + 0.29)'"
nrd="'0.29 / W'" nrs="'0.29 / W'"
sa=0 sb=0 sd=0
model=pfet_01v8
spiceprefix=X
}
C {sky130_fd_pr/pfet_01v8.sym} 170 -1390 1 0 {name=M71
W=1
L=0.4
nf=1
mult=1
ad="'int((nf+1)/2) * W/nf * 0.29'" 
pd="'2*int((nf+1)/2) * (W/nf + 0.29)'"
as="'int((nf+2)/2) * W/nf * 0.29'" 
ps="'2*int((nf+2)/2) * (W/nf + 0.29)'"
nrd="'0.29 / W'" nrs="'0.29 / W'"
sa=0 sb=0 sd=0
model=pfet_01v8
spiceprefix=X
}
C {sky130_fd_pr/pfet_01v8.sym} -90 -1390 3 1 {name=M72
W=1
L=0.4
nf=1
mult=1
ad="'int((nf+1)/2) * W/nf * 0.29'" 
pd="'2*int((nf+1)/2) * (W/nf + 0.29)'"
as="'int((nf+2)/2) * W/nf * 0.29'" 
ps="'2*int((nf+2)/2) * (W/nf + 0.29)'"
nrd="'0.29 / W'" nrs="'0.29 / W'"
sa=0 sb=0 sd=0
model=pfet_01v8
spiceprefix=X
}
C {sky130_fd_pr/pfet_01v8.sym} -20 -1390 1 0 {name=M73
W=1
L=0.4
nf=1
mult=1
ad="'int((nf+1)/2) * W/nf * 0.29'" 
pd="'2*int((nf+1)/2) * (W/nf + 0.29)'"
as="'int((nf+2)/2) * W/nf * 0.29'" 
ps="'2*int((nf+2)/2) * (W/nf + 0.29)'"
nrd="'0.29 / W'" nrs="'0.29 / W'"
sa=0 sb=0 sd=0
model=pfet_01v8
spiceprefix=X
}
C {sky130_fd_pr/pfet_01v8.sym} 100 -1480 3 0 {name=M74
W=1
L=0.4
nf=1
mult=1
ad="'int((nf+1)/2) * W/nf * 0.29'" 
pd="'2*int((nf+1)/2) * (W/nf + 0.29)'"
as="'int((nf+2)/2) * W/nf * 0.29'" 
ps="'2*int((nf+2)/2) * (W/nf + 0.29)'"
nrd="'0.29 / W'" nrs="'0.29 / W'"
sa=0 sb=0 sd=0
model=pfet_01v8
spiceprefix=X
}
C {sky130_fd_pr/pfet_01v8.sym} 170 -1480 1 1 {name=M75
W=1
L=0.4
nf=1
mult=1
ad="'int((nf+1)/2) * W/nf * 0.29'" 
pd="'2*int((nf+1)/2) * (W/nf + 0.29)'"
as="'int((nf+2)/2) * W/nf * 0.29'" 
ps="'2*int((nf+2)/2) * (W/nf + 0.29)'"
nrd="'0.29 / W'" nrs="'0.29 / W'"
sa=0 sb=0 sd=0
model=pfet_01v8
spiceprefix=X
}
C {sky130_fd_pr/pfet_01v8.sym} -90 -1620 1 1 {name=M76
W=1
L=0.4
nf=1
mult=1
ad="'int((nf+1)/2) * W/nf * 0.29'" 
pd="'2*int((nf+1)/2) * (W/nf + 0.29)'"
as="'int((nf+2)/2) * W/nf * 0.29'" 
ps="'2*int((nf+2)/2) * (W/nf + 0.29)'"
nrd="'0.29 / W'" nrs="'0.29 / W'"
sa=0 sb=0 sd=0
model=pfet_01v8
spiceprefix=X
}
C {sky130_fd_pr/pfet_01v8.sym} -10 -1620 3 0 {name=M78
W=1
L=0.4
nf=1
mult=1
ad="'int((nf+1)/2) * W/nf * 0.29'" 
pd="'2*int((nf+1)/2) * (W/nf + 0.29)'"
as="'int((nf+2)/2) * W/nf * 0.29'" 
ps="'2*int((nf+2)/2) * (W/nf + 0.29)'"
nrd="'0.29 / W'" nrs="'0.29 / W'"
sa=0 sb=0 sd=0
model=pfet_01v8
spiceprefix=X
}
C {sky130_fd_pr/pfet_01v8.sym} 100 -1620 1 1 {name=M79
W=1
L=0.4
nf=1
mult=1
ad="'int((nf+1)/2) * W/nf * 0.29'" 
pd="'2*int((nf+1)/2) * (W/nf + 0.29)'"
as="'int((nf+2)/2) * W/nf * 0.29'" 
ps="'2*int((nf+2)/2) * (W/nf + 0.29)'"
nrd="'0.29 / W'" nrs="'0.29 / W'"
sa=0 sb=0 sd=0
model=pfet_01v8
spiceprefix=X
}
C {sky130_fd_pr/pfet_01v8.sym} 170 -1620 3 0 {name=M80
W=1
L=0.4
nf=1
mult=1
ad="'int((nf+1)/2) * W/nf * 0.29'" 
pd="'2*int((nf+1)/2) * (W/nf + 0.29)'"
as="'int((nf+2)/2) * W/nf * 0.29'" 
ps="'2*int((nf+2)/2) * (W/nf + 0.29)'"
nrd="'0.29 / W'" nrs="'0.29 / W'"
sa=0 sb=0 sd=0
model=pfet_01v8
spiceprefix=X
}
C {sky130_fd_pr/pfet_01v8.sym} -90 -1220 1 0 {name=M81
W=1
L=0.4
nf=1
mult=1
ad="'int((nf+1)/2) * W/nf * 0.29'" 
pd="'2*int((nf+1)/2) * (W/nf + 0.29)'"
as="'int((nf+2)/2) * W/nf * 0.29'" 
ps="'2*int((nf+2)/2) * (W/nf + 0.29)'"
nrd="'0.29 / W'" nrs="'0.29 / W'"
sa=0 sb=0 sd=0
model=pfet_01v8
spiceprefix=X
}
C {sky130_fd_pr/pfet_01v8.sym} -20 -1220 3 1 {name=M82
W=1
L=0.4
nf=1
mult=1
ad="'int((nf+1)/2) * W/nf * 0.29'" 
pd="'2*int((nf+1)/2) * (W/nf + 0.29)'"
as="'int((nf+2)/2) * W/nf * 0.29'" 
ps="'2*int((nf+2)/2) * (W/nf + 0.29)'"
nrd="'0.29 / W'" nrs="'0.29 / W'"
sa=0 sb=0 sd=0
model=pfet_01v8
spiceprefix=X
}
C {sky130_fd_pr/pfet_01v8.sym} 100 -1220 1 0 {name=M83
W=1
L=0.4
nf=1
mult=1
ad="'int((nf+1)/2) * W/nf * 0.29'" 
pd="'2*int((nf+1)/2) * (W/nf + 0.29)'"
as="'int((nf+2)/2) * W/nf * 0.29'" 
ps="'2*int((nf+2)/2) * (W/nf + 0.29)'"
nrd="'0.29 / W'" nrs="'0.29 / W'"
sa=0 sb=0 sd=0
model=pfet_01v8
spiceprefix=X
}
C {sky130_fd_pr/pfet_01v8.sym} 170 -1220 3 1 {name=M84
W=1
L=0.4
nf=1
mult=1
ad="'int((nf+1)/2) * W/nf * 0.29'" 
pd="'2*int((nf+1)/2) * (W/nf + 0.29)'"
as="'int((nf+2)/2) * W/nf * 0.29'" 
ps="'2*int((nf+2)/2) * (W/nf + 0.29)'"
nrd="'0.29 / W'" nrs="'0.29 / W'"
sa=0 sb=0 sd=0
model=pfet_01v8
spiceprefix=X
}
C {sky130_fd_pr/pfet_01v8.sym} 250 -1620 1 1 {name=M87
W=1
L=0.4
nf=1
mult=1
ad="'int((nf+1)/2) * W/nf * 0.29'" 
pd="'2*int((nf+1)/2) * (W/nf + 0.29)'"
as="'int((nf+2)/2) * W/nf * 0.29'" 
ps="'2*int((nf+2)/2) * (W/nf + 0.29)'"
nrd="'0.29 / W'" nrs="'0.29 / W'"
sa=0 sb=0 sd=0
model=pfet_01v8
spiceprefix=X
}
C {sky130_fd_pr/pfet_01v8.sym} 250 -1220 1 0 {name=M88
W=1
L=0.4
nf=1
mult=1
ad="'int((nf+1)/2) * W/nf * 0.29'" 
pd="'2*int((nf+1)/2) * (W/nf + 0.29)'"
as="'int((nf+2)/2) * W/nf * 0.29'" 
ps="'2*int((nf+2)/2) * (W/nf + 0.29)'"
nrd="'0.29 / W'" nrs="'0.29 / W'"
sa=0 sb=0 sd=0
model=pfet_01v8
spiceprefix=X
}
C {sky130_fd_pr/pfet_01v8.sym} -170 -1620 3 0 {name=M91
W=1
L=0.4
nf=1
mult=1
ad="'int((nf+1)/2) * W/nf * 0.29'" 
pd="'2*int((nf+1)/2) * (W/nf + 0.29)'"
as="'int((nf+2)/2) * W/nf * 0.29'" 
ps="'2*int((nf+2)/2) * (W/nf + 0.29)'"
nrd="'0.29 / W'" nrs="'0.29 / W'"
sa=0 sb=0 sd=0
model=pfet_01v8
spiceprefix=X
}
C {sky130_fd_pr/pfet_01v8.sym} -170 -1220 3 1 {name=M92
W=1
L=0.4
nf=1
mult=1
ad="'int((nf+1)/2) * W/nf * 0.29'" 
pd="'2*int((nf+1)/2) * (W/nf + 0.29)'"
as="'int((nf+2)/2) * W/nf * 0.29'" 
ps="'2*int((nf+2)/2) * (W/nf + 0.29)'"
nrd="'0.29 / W'" nrs="'0.29 / W'"
sa=0 sb=0 sd=0
model=pfet_01v8
spiceprefix=X
}
C {sky130_fd_pr/pfet_01v8.sym} -360 -1220 1 0 {name=M97
W=1
L=0.4
nf=1
mult=1
ad="'int((nf+1)/2) * W/nf * 0.29'" 
pd="'2*int((nf+1)/2) * (W/nf + 0.29)'"
as="'int((nf+2)/2) * W/nf * 0.29'" 
ps="'2*int((nf+2)/2) * (W/nf + 0.29)'"
nrd="'0.29 / W'" nrs="'0.29 / W'"
sa=0 sb=0 sd=0
model=pfet_01v8
spiceprefix=X
}
C {sky130_fd_pr/pfet_01v8.sym} 520 -1220 3 1 {name=M98
W=1
L=0.4
nf=1
mult=1
ad="'int((nf+1)/2) * W/nf * 0.29'" 
pd="'2*int((nf+1)/2) * (W/nf + 0.29)'"
as="'int((nf+2)/2) * W/nf * 0.29'" 
ps="'2*int((nf+2)/2) * (W/nf + 0.29)'"
nrd="'0.29 / W'" nrs="'0.29 / W'"
sa=0 sb=0 sd=0
model=pfet_01v8
spiceprefix=X
}
C {sky130_fd_pr/pfet_01v8.sym} -250 -1620 1 1 {name=M99
W=1
L=0.4
nf=1
mult=1
ad="'int((nf+1)/2) * W/nf * 0.29'" 
pd="'2*int((nf+1)/2) * (W/nf + 0.29)'"
as="'int((nf+2)/2) * W/nf * 0.29'" 
ps="'2*int((nf+2)/2) * (W/nf + 0.29)'"
nrd="'0.29 / W'" nrs="'0.29 / W'"
sa=0 sb=0 sd=0
model=pfet_01v8
spiceprefix=X
}
C {sky130_fd_pr/pfet_01v8.sym} 420 -1620 3 0 {name=M100
W=1
L=0.4
nf=1
mult=1
ad="'int((nf+1)/2) * W/nf * 0.29'" 
pd="'2*int((nf+1)/2) * (W/nf + 0.29)'"
as="'int((nf+2)/2) * W/nf * 0.29'" 
ps="'2*int((nf+2)/2) * (W/nf + 0.29)'"
nrd="'0.29 / W'" nrs="'0.29 / W'"
sa=0 sb=0 sd=0
model=pfet_01v8
spiceprefix=X
}
C {sky130_fd_pr/pfet_01v8.sym} -410 -1620 1 1 {name=M3
W=1
L=0.4
nf=1
mult=1
ad="'int((nf+1)/2) * W/nf * 0.29'" 
pd="'2*int((nf+1)/2) * (W/nf + 0.29)'"
as="'int((nf+2)/2) * W/nf * 0.29'" 
ps="'2*int((nf+2)/2) * (W/nf + 0.29)'"
nrd="'0.29 / W'" nrs="'0.29 / W'"
sa=0 sb=0 sd=0
model=pfet_01v8
spiceprefix=X
}
C {sky130_fd_pr/pfet_01v8.sym} 330 -1220 3 1 {name=M4
W=1
L=0.4
nf=1
mult=1
ad="'int((nf+1)/2) * W/nf * 0.29'" 
pd="'2*int((nf+1)/2) * (W/nf + 0.29)'"
as="'int((nf+2)/2) * W/nf * 0.29'" 
ps="'2*int((nf+2)/2) * (W/nf + 0.29)'"
nrd="'0.29 / W'" nrs="'0.29 / W'"
sa=0 sb=0 sd=0
model=pfet_01v8
spiceprefix=X
}
C {sky130_fd_pr/pfet_01v8.sym} -330 -1620 3 0 {name=M7
W=1
L=0.4
nf=1
mult=1
ad="'int((nf+1)/2) * W/nf * 0.29'" 
pd="'2*int((nf+1)/2) * (W/nf + 0.29)'"
as="'int((nf+2)/2) * W/nf * 0.29'" 
ps="'2*int((nf+2)/2) * (W/nf + 0.29)'"
nrd="'0.29 / W'" nrs="'0.29 / W'"
sa=0 sb=0 sd=0
model=pfet_01v8
spiceprefix=X
}
C {sky130_fd_pr/pfet_01v8.sym} 330 -1620 3 0 {name=M12
W=1
L=0.4
nf=1
mult=1
ad="'int((nf+1)/2) * W/nf * 0.29'" 
pd="'2*int((nf+1)/2) * (W/nf + 0.29)'"
as="'int((nf+2)/2) * W/nf * 0.29'" 
ps="'2*int((nf+2)/2) * (W/nf + 0.29)'"
nrd="'0.29 / W'" nrs="'0.29 / W'"
sa=0 sb=0 sd=0
model=pfet_01v8
spiceprefix=X
}
C {sky130_fd_pr/pfet_01v8.sym} 490 -1620 3 0 {name=M64
W=1
L=0.4
nf=1
mult=1
ad="'int((nf+1)/2) * W/nf * 0.29'" 
pd="'2*int((nf+1)/2) * (W/nf + 0.29)'"
as="'int((nf+2)/2) * W/nf * 0.29'" 
ps="'2*int((nf+2)/2) * (W/nf + 0.29)'"
nrd="'0.29 / W'" nrs="'0.29 / W'"
sa=0 sb=0 sd=0
model=pfet_01v8
spiceprefix=X
}
C {sky130_fd_pr/pfet_01v8.sym} -170 -1480 1 1 {name=M65
W=1
L=0.4
nf=1
mult=1
ad="'int((nf+1)/2) * W/nf * 0.29'" 
pd="'2*int((nf+1)/2) * (W/nf + 0.29)'"
as="'int((nf+2)/2) * W/nf * 0.29'" 
ps="'2*int((nf+2)/2) * (W/nf + 0.29)'"
nrd="'0.29 / W'" nrs="'0.29 / W'"
sa=0 sb=0 sd=0
model=pfet_01v8
spiceprefix=X
}
C {sky130_fd_pr/pfet_01v8.sym} 250 -1480 3 0 {name=M66
W=1
L=0.4
nf=1
mult=1
ad="'int((nf+1)/2) * W/nf * 0.29'" 
pd="'2*int((nf+1)/2) * (W/nf + 0.29)'"
as="'int((nf+2)/2) * W/nf * 0.29'" 
ps="'2*int((nf+2)/2) * (W/nf + 0.29)'"
nrd="'0.29 / W'" nrs="'0.29 / W'"
sa=0 sb=0 sd=0
model=pfet_01v8
spiceprefix=X
}
C {sky130_fd_pr/pfet_01v8.sym} -170 -1390 1 0 {name=M67
W=1
L=0.4
nf=1
mult=1
ad="'int((nf+1)/2) * W/nf * 0.29'" 
pd="'2*int((nf+1)/2) * (W/nf + 0.29)'"
as="'int((nf+2)/2) * W/nf * 0.29'" 
ps="'2*int((nf+2)/2) * (W/nf + 0.29)'"
nrd="'0.29 / W'" nrs="'0.29 / W'"
sa=0 sb=0 sd=0
model=pfet_01v8
spiceprefix=X
}
C {sky130_fd_pr/pfet_01v8.sym} 250 -1390 3 1 {name=M77
W=1
L=0.4
nf=1
mult=1
ad="'int((nf+1)/2) * W/nf * 0.29'" 
pd="'2*int((nf+1)/2) * (W/nf + 0.29)'"
as="'int((nf+2)/2) * W/nf * 0.29'" 
ps="'2*int((nf+2)/2) * (W/nf + 0.29)'"
nrd="'0.29 / W'" nrs="'0.29 / W'"
sa=0 sb=0 sd=0
model=pfet_01v8
spiceprefix=X
}
C {sky130_fd_pr/pfet_01v8.sym} -260 -1480 1 1 {name=M85
W=1
L=0.4
nf=1
mult=1
ad="'int((nf+1)/2) * W/nf * 0.29'" 
pd="'2*int((nf+1)/2) * (W/nf + 0.29)'"
as="'int((nf+2)/2) * W/nf * 0.29'" 
ps="'2*int((nf+2)/2) * (W/nf + 0.29)'"
nrd="'0.29 / W'" nrs="'0.29 / W'"
sa=0 sb=0 sd=0
model=pfet_01v8
spiceprefix=X
}
C {sky130_fd_pr/pfet_01v8.sym} -340 -1480 3 0 {name=M86
W=1
L=0.4
nf=1
mult=1
ad="'int((nf+1)/2) * W/nf * 0.29'" 
pd="'2*int((nf+1)/2) * (W/nf + 0.29)'"
as="'int((nf+2)/2) * W/nf * 0.29'" 
ps="'2*int((nf+2)/2) * (W/nf + 0.29)'"
nrd="'0.29 / W'" nrs="'0.29 / W'"
sa=0 sb=0 sd=0
model=pfet_01v8
spiceprefix=X
}
C {sky130_fd_pr/pfet_01v8.sym} -420 -1480 1 1 {name=M89
W=1
L=0.4
nf=1
mult=1
ad="'int((nf+1)/2) * W/nf * 0.29'" 
pd="'2*int((nf+1)/2) * (W/nf + 0.29)'"
as="'int((nf+2)/2) * W/nf * 0.29'" 
ps="'2*int((nf+2)/2) * (W/nf + 0.29)'"
nrd="'0.29 / W'" nrs="'0.29 / W'"
sa=0 sb=0 sd=0
model=pfet_01v8
spiceprefix=X
}
C {sky130_fd_pr/pfet_01v8.sym} 340 -1480 3 0 {name=M90
W=1
L=0.4
nf=1
mult=1
ad="'int((nf+1)/2) * W/nf * 0.29'" 
pd="'2*int((nf+1)/2) * (W/nf + 0.29)'"
as="'int((nf+2)/2) * W/nf * 0.29'" 
ps="'2*int((nf+2)/2) * (W/nf + 0.29)'"
nrd="'0.29 / W'" nrs="'0.29 / W'"
sa=0 sb=0 sd=0
model=pfet_01v8
spiceprefix=X
}
C {sky130_fd_pr/pfet_01v8.sym} 420 -1480 1 1 {name=M93
W=1
L=0.4
nf=1
mult=1
ad="'int((nf+1)/2) * W/nf * 0.29'" 
pd="'2*int((nf+1)/2) * (W/nf + 0.29)'"
as="'int((nf+2)/2) * W/nf * 0.29'" 
ps="'2*int((nf+2)/2) * (W/nf + 0.29)'"
nrd="'0.29 / W'" nrs="'0.29 / W'"
sa=0 sb=0 sd=0
model=pfet_01v8
spiceprefix=X
}
C {sky130_fd_pr/pfet_01v8.sym} 500 -1480 3 0 {name=M94
W=1
L=0.4
nf=1
mult=1
ad="'int((nf+1)/2) * W/nf * 0.29'" 
pd="'2*int((nf+1)/2) * (W/nf + 0.29)'"
as="'int((nf+2)/2) * W/nf * 0.29'" 
ps="'2*int((nf+2)/2) * (W/nf + 0.29)'"
nrd="'0.29 / W'" nrs="'0.29 / W'"
sa=0 sb=0 sd=0
model=pfet_01v8
spiceprefix=X
}
C {sky130_fd_pr/pfet_01v8.sym} -260 -1390 1 0 {name=M95
W=1
L=0.4
nf=1
mult=1
ad="'int((nf+1)/2) * W/nf * 0.29'" 
pd="'2*int((nf+1)/2) * (W/nf + 0.29)'"
as="'int((nf+2)/2) * W/nf * 0.29'" 
ps="'2*int((nf+2)/2) * (W/nf + 0.29)'"
nrd="'0.29 / W'" nrs="'0.29 / W'"
sa=0 sb=0 sd=0
model=pfet_01v8
spiceprefix=X
}
C {sky130_fd_pr/pfet_01v8.sym} -340 -1390 3 1 {name=M96
W=1
L=0.4
nf=1
mult=1
ad="'int((nf+1)/2) * W/nf * 0.29'" 
pd="'2*int((nf+1)/2) * (W/nf + 0.29)'"
as="'int((nf+2)/2) * W/nf * 0.29'" 
ps="'2*int((nf+2)/2) * (W/nf + 0.29)'"
nrd="'0.29 / W'" nrs="'0.29 / W'"
sa=0 sb=0 sd=0
model=pfet_01v8
spiceprefix=X
}
C {sky130_fd_pr/pfet_01v8.sym} -420 -1390 1 0 {name=M101
W=1
L=0.4
nf=1
mult=1
ad="'int((nf+1)/2) * W/nf * 0.29'" 
pd="'2*int((nf+1)/2) * (W/nf + 0.29)'"
as="'int((nf+2)/2) * W/nf * 0.29'" 
ps="'2*int((nf+2)/2) * (W/nf + 0.29)'"
nrd="'0.29 / W'" nrs="'0.29 / W'"
sa=0 sb=0 sd=0
model=pfet_01v8
spiceprefix=X
}
C {sky130_fd_pr/pfet_01v8.sym} 340 -1390 3 1 {name=M102
W=1
L=0.4
nf=1
mult=1
ad="'int((nf+1)/2) * W/nf * 0.29'" 
pd="'2*int((nf+1)/2) * (W/nf + 0.29)'"
as="'int((nf+2)/2) * W/nf * 0.29'" 
ps="'2*int((nf+2)/2) * (W/nf + 0.29)'"
nrd="'0.29 / W'" nrs="'0.29 / W'"
sa=0 sb=0 sd=0
model=pfet_01v8
spiceprefix=X
}
C {sky130_fd_pr/pfet_01v8.sym} 420 -1390 1 0 {name=M103
W=1
L=0.4
nf=1
mult=1
ad="'int((nf+1)/2) * W/nf * 0.29'" 
pd="'2*int((nf+1)/2) * (W/nf + 0.29)'"
as="'int((nf+2)/2) * W/nf * 0.29'" 
ps="'2*int((nf+2)/2) * (W/nf + 0.29)'"
nrd="'0.29 / W'" nrs="'0.29 / W'"
sa=0 sb=0 sd=0
model=pfet_01v8
spiceprefix=X
}
C {sky130_fd_pr/pfet_01v8.sym} 500 -1390 3 1 {name=M104
W=1
L=0.4
nf=1
mult=1
ad="'int((nf+1)/2) * W/nf * 0.29'" 
pd="'2*int((nf+1)/2) * (W/nf + 0.29)'"
as="'int((nf+2)/2) * W/nf * 0.29'" 
ps="'2*int((nf+2)/2) * (W/nf + 0.29)'"
nrd="'0.29 / W'" nrs="'0.29 / W'"
sa=0 sb=0 sd=0
model=pfet_01v8
spiceprefix=X
}
C {sky130_fd_pr/pfet_01v8.sym} -250 -1220 1 0 {name=M105
W=1
L=0.4
nf=1
mult=1
ad="'int((nf+1)/2) * W/nf * 0.29'" 
pd="'2*int((nf+1)/2) * (W/nf + 0.29)'"
as="'int((nf+2)/2) * W/nf * 0.29'" 
ps="'2*int((nf+2)/2) * (W/nf + 0.29)'"
nrd="'0.29 / W'" nrs="'0.29 / W'"
sa=0 sb=0 sd=0
model=pfet_01v8
spiceprefix=X
}
C {sky130_fd_pr/pfet_01v8.sym} -430 -1220 1 0 {name=M106
W=1
L=0.4
nf=1
mult=1
ad="'int((nf+1)/2) * W/nf * 0.29'" 
pd="'2*int((nf+1)/2) * (W/nf + 0.29)'"
as="'int((nf+2)/2) * W/nf * 0.29'" 
ps="'2*int((nf+2)/2) * (W/nf + 0.29)'"
nrd="'0.29 / W'" nrs="'0.29 / W'"
sa=0 sb=0 sd=0
model=pfet_01v8
spiceprefix=X
}
C {sky130_fd_pr/pfet_01v8.sym} 410 -1220 1 0 {name=M107
W=1
L=0.4
nf=1
mult=1
ad="'int((nf+1)/2) * W/nf * 0.29'" 
pd="'2*int((nf+1)/2) * (W/nf + 0.29)'"
as="'int((nf+2)/2) * W/nf * 0.29'" 
ps="'2*int((nf+2)/2) * (W/nf + 0.29)'"
nrd="'0.29 / W'" nrs="'0.29 / W'"
sa=0 sb=0 sd=0
model=pfet_01v8
spiceprefix=X
}
C {sky130_fd_pr/nfet_01v8_lvt.sym} -470 -250 3 1 {name=M1
W=7
L=1
nf=1
mult=1
ad="expr('int((@nf + 1)/2) * @W / @nf * 0.29')"
pd="expr('2*int((@nf + 1)/2) * (@W / @nf + 0.29)')"
as="expr('int((@nf + 2)/2) * @W / @nf * 0.29')"
ps="expr('2*int((@nf + 2)/2) * (@W / @nf + 0.29)')"
nrd="expr('0.29 / @W ')" nrs="expr('0.29 / @W ')"
sa=0 sb=0 sd=0
model=nfet_01v8_lvt
spiceprefix=X
}
C {sky130_fd_pr/nfet_01v8_lvt.sym} -400 -250 1 0 {name=M2
W=7
L=1
nf=1
mult=1
ad="expr('int((@nf + 1)/2) * @W / @nf * 0.29')"
pd="expr('2*int((@nf + 1)/2) * (@W / @nf + 0.29)')"
as="expr('int((@nf + 2)/2) * @W / @nf * 0.29')"
ps="expr('2*int((@nf + 2)/2) * (@W / @nf + 0.29)')"
nrd="expr('0.29 / @W ')" nrs="expr('0.29 / @W ')"
sa=0 sb=0 sd=0
model=nfet_01v8_lvt
spiceprefix=X
}
C {sky130_fd_pr/nfet_01v8_lvt.sym} -330 -250 3 1 {name=M108
W=7
L=1
nf=1
mult=1
ad="expr('int((@nf + 1)/2) * @W / @nf * 0.29')"
pd="expr('2*int((@nf + 1)/2) * (@W / @nf + 0.29)')"
as="expr('int((@nf + 2)/2) * @W / @nf * 0.29')"
ps="expr('2*int((@nf + 2)/2) * (@W / @nf + 0.29)')"
nrd="expr('0.29 / @W ')" nrs="expr('0.29 / @W ')"
sa=0 sb=0 sd=0
model=nfet_01v8_lvt
spiceprefix=X
}
C {sky130_fd_pr/nfet_01v8_lvt.sym} -260 -250 1 0 {name=M109
W=7
L=1
nf=1
mult=1
ad="expr('int((@nf + 1)/2) * @W / @nf * 0.29')"
pd="expr('2*int((@nf + 1)/2) * (@W / @nf + 0.29)')"
as="expr('int((@nf + 2)/2) * @W / @nf * 0.29')"
ps="expr('2*int((@nf + 2)/2) * (@W / @nf + 0.29)')"
nrd="expr('0.29 / @W ')" nrs="expr('0.29 / @W ')"
sa=0 sb=0 sd=0
model=nfet_01v8_lvt
spiceprefix=X
}
C {sky130_fd_pr/nfet_01v8_lvt.sym} -190 -250 3 1 {name=M110
W=7
L=1
nf=1
mult=1
ad="expr('int((@nf + 1)/2) * @W / @nf * 0.29')"
pd="expr('2*int((@nf + 1)/2) * (@W / @nf + 0.29)')"
as="expr('int((@nf + 2)/2) * @W / @nf * 0.29')"
ps="expr('2*int((@nf + 2)/2) * (@W / @nf + 0.29)')"
nrd="expr('0.29 / @W ')" nrs="expr('0.29 / @W ')"
sa=0 sb=0 sd=0
model=nfet_01v8_lvt
spiceprefix=X
}
C {sky130_fd_pr/nfet_01v8_lvt.sym} -120 -250 1 0 {name=M111
W=7
L=1
nf=1
mult=1
ad="expr('int((@nf + 1)/2) * @W / @nf * 0.29')"
pd="expr('2*int((@nf + 1)/2) * (@W / @nf + 0.29)')"
as="expr('int((@nf + 2)/2) * @W / @nf * 0.29')"
ps="expr('2*int((@nf + 2)/2) * (@W / @nf + 0.29)')"
nrd="expr('0.29 / @W ')" nrs="expr('0.29 / @W ')"
sa=0 sb=0 sd=0
model=nfet_01v8_lvt
spiceprefix=X
}
C {sky130_fd_pr/nfet_01v8_lvt.sym} -50 -250 3 1 {name=M112
W=7
L=1
nf=1
mult=1
ad="expr('int((@nf + 1)/2) * @W / @nf * 0.29')"
pd="expr('2*int((@nf + 1)/2) * (@W / @nf + 0.29)')"
as="expr('int((@nf + 2)/2) * @W / @nf * 0.29')"
ps="expr('2*int((@nf + 2)/2) * (@W / @nf + 0.29)')"
nrd="expr('0.29 / @W ')" nrs="expr('0.29 / @W ')"
sa=0 sb=0 sd=0
model=nfet_01v8_lvt
spiceprefix=X
}
C {sky130_fd_pr/nfet_01v8_lvt.sym} 20 -250 1 0 {name=M113
W=7
L=1
nf=1
mult=1
ad="expr('int((@nf + 1)/2) * @W / @nf * 0.29')"
pd="expr('2*int((@nf + 1)/2) * (@W / @nf + 0.29)')"
as="expr('int((@nf + 2)/2) * @W / @nf * 0.29')"
ps="expr('2*int((@nf + 2)/2) * (@W / @nf + 0.29)')"
nrd="expr('0.29 / @W ')" nrs="expr('0.29 / @W ')"
sa=0 sb=0 sd=0
model=nfet_01v8_lvt
spiceprefix=X
}
C {sky130_fd_pr/nfet_01v8_lvt.sym} -470 -30 3 0 {name=M114
W=7
L=1
nf=1
mult=1
ad="expr('int((@nf + 1)/2) * @W / @nf * 0.29')"
pd="expr('2*int((@nf + 1)/2) * (@W / @nf + 0.29)')"
as="expr('int((@nf + 2)/2) * @W / @nf * 0.29')"
ps="expr('2*int((@nf + 2)/2) * (@W / @nf + 0.29)')"
nrd="expr('0.29 / @W ')" nrs="expr('0.29 / @W ')"
sa=0 sb=0 sd=0
model=nfet_01v8_lvt
spiceprefix=X
}
C {sky130_fd_pr/nfet_01v8_lvt.sym} -400 -30 1 1 {name=M115
W=7
L=1
nf=1
mult=1
ad="expr('int((@nf + 1)/2) * @W / @nf * 0.29')"
pd="expr('2*int((@nf + 1)/2) * (@W / @nf + 0.29)')"
as="expr('int((@nf + 2)/2) * @W / @nf * 0.29')"
ps="expr('2*int((@nf + 2)/2) * (@W / @nf + 0.29)')"
nrd="expr('0.29 / @W ')" nrs="expr('0.29 / @W ')"
sa=0 sb=0 sd=0
model=nfet_01v8_lvt
spiceprefix=X
}
C {sky130_fd_pr/nfet_01v8_lvt.sym} -330 -30 3 0 {name=M116
W=7
L=1
nf=1
mult=1
ad="expr('int((@nf + 1)/2) * @W / @nf * 0.29')"
pd="expr('2*int((@nf + 1)/2) * (@W / @nf + 0.29)')"
as="expr('int((@nf + 2)/2) * @W / @nf * 0.29')"
ps="expr('2*int((@nf + 2)/2) * (@W / @nf + 0.29)')"
nrd="expr('0.29 / @W ')" nrs="expr('0.29 / @W ')"
sa=0 sb=0 sd=0
model=nfet_01v8_lvt
spiceprefix=X
}
C {sky130_fd_pr/nfet_01v8_lvt.sym} -260 -30 1 1 {name=M117
W=7
L=1
nf=1
mult=1
ad="expr('int((@nf + 1)/2) * @W / @nf * 0.29')"
pd="expr('2*int((@nf + 1)/2) * (@W / @nf + 0.29)')"
as="expr('int((@nf + 2)/2) * @W / @nf * 0.29')"
ps="expr('2*int((@nf + 2)/2) * (@W / @nf + 0.29)')"
nrd="expr('0.29 / @W ')" nrs="expr('0.29 / @W ')"
sa=0 sb=0 sd=0
model=nfet_01v8_lvt
spiceprefix=X
}
C {sky130_fd_pr/nfet_01v8_lvt.sym} -190 -30 3 0 {name=M118
W=7
L=1
nf=1
mult=1
ad="expr('int((@nf + 1)/2) * @W / @nf * 0.29')"
pd="expr('2*int((@nf + 1)/2) * (@W / @nf + 0.29)')"
as="expr('int((@nf + 2)/2) * @W / @nf * 0.29')"
ps="expr('2*int((@nf + 2)/2) * (@W / @nf + 0.29)')"
nrd="expr('0.29 / @W ')" nrs="expr('0.29 / @W ')"
sa=0 sb=0 sd=0
model=nfet_01v8_lvt
spiceprefix=X
}
C {sky130_fd_pr/nfet_01v8_lvt.sym} -120 -30 1 1 {name=M119
W=7
L=1
nf=1
mult=1
ad="expr('int((@nf + 1)/2) * @W / @nf * 0.29')"
pd="expr('2*int((@nf + 1)/2) * (@W / @nf + 0.29)')"
as="expr('int((@nf + 2)/2) * @W / @nf * 0.29')"
ps="expr('2*int((@nf + 2)/2) * (@W / @nf + 0.29)')"
nrd="expr('0.29 / @W ')" nrs="expr('0.29 / @W ')"
sa=0 sb=0 sd=0
model=nfet_01v8_lvt
spiceprefix=X
}
C {sky130_fd_pr/nfet_01v8_lvt.sym} -50 -30 3 0 {name=M120
W=7
L=1
nf=1
mult=1
ad="expr('int((@nf + 1)/2) * @W / @nf * 0.29')"
pd="expr('2*int((@nf + 1)/2) * (@W / @nf + 0.29)')"
as="expr('int((@nf + 2)/2) * @W / @nf * 0.29')"
ps="expr('2*int((@nf + 2)/2) * (@W / @nf + 0.29)')"
nrd="expr('0.29 / @W ')" nrs="expr('0.29 / @W ')"
sa=0 sb=0 sd=0
model=nfet_01v8_lvt
spiceprefix=X
}
C {sky130_fd_pr/nfet_01v8_lvt.sym} 20 -30 1 1 {name=M121
W=7
L=1
nf=1
mult=1
ad="expr('int((@nf + 1)/2) * @W / @nf * 0.29')"
pd="expr('2*int((@nf + 1)/2) * (@W / @nf + 0.29)')"
as="expr('int((@nf + 2)/2) * @W / @nf * 0.29')"
ps="expr('2*int((@nf + 2)/2) * (@W / @nf + 0.29)')"
nrd="expr('0.29 / @W ')" nrs="expr('0.29 / @W ')"
sa=0 sb=0 sd=0
model=nfet_01v8_lvt
spiceprefix=X
}
C {sky130_fd_pr/nfet_01v8_lvt.sym} -450 -530 3 1 {name=M126
W=7
L=1
nf=1
mult=1
ad="expr('int((@nf + 1)/2) * @W / @nf * 0.29')"
pd="expr('2*int((@nf + 1)/2) * (@W / @nf + 0.29)')"
as="expr('int((@nf + 2)/2) * @W / @nf * 0.29')"
ps="expr('2*int((@nf + 2)/2) * (@W / @nf + 0.29)')"
nrd="expr('0.29 / @W ')" nrs="expr('0.29 / @W ')"
sa=0 sb=0 sd=0
model=nfet_01v8_lvt
spiceprefix=X
}
C {sky130_fd_pr/nfet_01v8_lvt.sym} -380 -530 1 0 {name=M127
W=7
L=1
nf=1
mult=1
ad="expr('int((@nf + 1)/2) * @W / @nf * 0.29')"
pd="expr('2*int((@nf + 1)/2) * (@W / @nf + 0.29)')"
as="expr('int((@nf + 2)/2) * @W / @nf * 0.29')"
ps="expr('2*int((@nf + 2)/2) * (@W / @nf + 0.29)')"
nrd="expr('0.29 / @W ')" nrs="expr('0.29 / @W ')"
sa=0 sb=0 sd=0
model=nfet_01v8_lvt
spiceprefix=X
}
C {sky130_fd_pr/nfet_01v8_lvt.sym} -310 -530 3 1 {name=M128
W=7
L=1
nf=1
mult=1
ad="expr('int((@nf + 1)/2) * @W / @nf * 0.29')"
pd="expr('2*int((@nf + 1)/2) * (@W / @nf + 0.29)')"
as="expr('int((@nf + 2)/2) * @W / @nf * 0.29')"
ps="expr('2*int((@nf + 2)/2) * (@W / @nf + 0.29)')"
nrd="expr('0.29 / @W ')" nrs="expr('0.29 / @W ')"
sa=0 sb=0 sd=0
model=nfet_01v8_lvt
spiceprefix=X
}
C {sky130_fd_pr/nfet_01v8_lvt.sym} -240 -530 1 0 {name=M129
W=7
L=1
nf=1
mult=1
ad="expr('int((@nf + 1)/2) * @W / @nf * 0.29')"
pd="expr('2*int((@nf + 1)/2) * (@W / @nf + 0.29)')"
as="expr('int((@nf + 2)/2) * @W / @nf * 0.29')"
ps="expr('2*int((@nf + 2)/2) * (@W / @nf + 0.29)')"
nrd="expr('0.29 / @W ')" nrs="expr('0.29 / @W ')"
sa=0 sb=0 sd=0
model=nfet_01v8_lvt
spiceprefix=X
}
C {sky130_fd_pr/nfet_01v8_lvt.sym} -170 -530 3 1 {name=M130
W=7
L=1
nf=1
mult=1
ad="expr('int((@nf + 1)/2) * @W / @nf * 0.29')"
pd="expr('2*int((@nf + 1)/2) * (@W / @nf + 0.29)')"
as="expr('int((@nf + 2)/2) * @W / @nf * 0.29')"
ps="expr('2*int((@nf + 2)/2) * (@W / @nf + 0.29)')"
nrd="expr('0.29 / @W ')" nrs="expr('0.29 / @W ')"
sa=0 sb=0 sd=0
model=nfet_01v8_lvt
spiceprefix=X
}
C {sky130_fd_pr/nfet_01v8_lvt.sym} -100 -530 1 0 {name=M131
W=7
L=1
nf=1
mult=1
ad="expr('int((@nf + 1)/2) * @W / @nf * 0.29')"
pd="expr('2*int((@nf + 1)/2) * (@W / @nf + 0.29)')"
as="expr('int((@nf + 2)/2) * @W / @nf * 0.29')"
ps="expr('2*int((@nf + 2)/2) * (@W / @nf + 0.29)')"
nrd="expr('0.29 / @W ')" nrs="expr('0.29 / @W ')"
sa=0 sb=0 sd=0
model=nfet_01v8_lvt
spiceprefix=X
}
C {sky130_fd_pr/nfet_01v8_lvt.sym} -30 -530 3 1 {name=M132
W=7
L=1
nf=1
mult=1
ad="expr('int((@nf + 1)/2) * @W / @nf * 0.29')"
pd="expr('2*int((@nf + 1)/2) * (@W / @nf + 0.29)')"
as="expr('int((@nf + 2)/2) * @W / @nf * 0.29')"
ps="expr('2*int((@nf + 2)/2) * (@W / @nf + 0.29)')"
nrd="expr('0.29 / @W ')" nrs="expr('0.29 / @W ')"
sa=0 sb=0 sd=0
model=nfet_01v8_lvt
spiceprefix=X
}
C {sky130_fd_pr/nfet_01v8_lvt.sym} 40 -530 1 0 {name=M133
W=7
L=1
nf=1
mult=1
ad="expr('int((@nf + 1)/2) * @W / @nf * 0.29')"
pd="expr('2*int((@nf + 1)/2) * (@W / @nf + 0.29)')"
as="expr('int((@nf + 2)/2) * @W / @nf * 0.29')"
ps="expr('2*int((@nf + 2)/2) * (@W / @nf + 0.29)')"
nrd="expr('0.29 / @W ')" nrs="expr('0.29 / @W ')"
sa=0 sb=0 sd=0
model=nfet_01v8_lvt
spiceprefix=X
}
C {lab_wire.sym} -140 -510 2 0 {name=p2 sig_type=std_logic lab=VSS}
C {sky130_fd_pr/nfet_01v8_lvt.sym} -510 230 3 1 {name=M134
W=7
L=1
nf=1
mult=1
ad="expr('int((@nf + 1)/2) * @W / @nf * 0.29')"
pd="expr('2*int((@nf + 1)/2) * (@W / @nf + 0.29)')"
as="expr('int((@nf + 2)/2) * @W / @nf * 0.29')"
ps="expr('2*int((@nf + 2)/2) * (@W / @nf + 0.29)')"
nrd="expr('0.29 / @W ')" nrs="expr('0.29 / @W ')"
sa=0 sb=0 sd=0
model=nfet_01v8_lvt
spiceprefix=X
}
C {sky130_fd_pr/nfet_01v8_lvt.sym} -440 230 1 0 {name=M135
W=7
L=1
nf=1
mult=1
ad="expr('int((@nf + 1)/2) * @W / @nf * 0.29')"
pd="expr('2*int((@nf + 1)/2) * (@W / @nf + 0.29)')"
as="expr('int((@nf + 2)/2) * @W / @nf * 0.29')"
ps="expr('2*int((@nf + 2)/2) * (@W / @nf + 0.29)')"
nrd="expr('0.29 / @W ')" nrs="expr('0.29 / @W ')"
sa=0 sb=0 sd=0
model=nfet_01v8_lvt
spiceprefix=X
}
C {sky130_fd_pr/nfet_01v8_lvt.sym} -370 230 3 1 {name=M136
W=7
L=1
nf=1
mult=1
ad="expr('int((@nf + 1)/2) * @W / @nf * 0.29')"
pd="expr('2*int((@nf + 1)/2) * (@W / @nf + 0.29)')"
as="expr('int((@nf + 2)/2) * @W / @nf * 0.29')"
ps="expr('2*int((@nf + 2)/2) * (@W / @nf + 0.29)')"
nrd="expr('0.29 / @W ')" nrs="expr('0.29 / @W ')"
sa=0 sb=0 sd=0
model=nfet_01v8_lvt
spiceprefix=X
}
C {sky130_fd_pr/nfet_01v8_lvt.sym} -300 230 1 0 {name=M137
W=7
L=1
nf=1
mult=1
ad="expr('int((@nf + 1)/2) * @W / @nf * 0.29')"
pd="expr('2*int((@nf + 1)/2) * (@W / @nf + 0.29)')"
as="expr('int((@nf + 2)/2) * @W / @nf * 0.29')"
ps="expr('2*int((@nf + 2)/2) * (@W / @nf + 0.29)')"
nrd="expr('0.29 / @W ')" nrs="expr('0.29 / @W ')"
sa=0 sb=0 sd=0
model=nfet_01v8_lvt
spiceprefix=X
}
C {sky130_fd_pr/nfet_01v8_lvt.sym} -230 230 3 1 {name=M138
W=7
L=1
nf=1
mult=1
ad="expr('int((@nf + 1)/2) * @W / @nf * 0.29')"
pd="expr('2*int((@nf + 1)/2) * (@W / @nf + 0.29)')"
as="expr('int((@nf + 2)/2) * @W / @nf * 0.29')"
ps="expr('2*int((@nf + 2)/2) * (@W / @nf + 0.29)')"
nrd="expr('0.29 / @W ')" nrs="expr('0.29 / @W ')"
sa=0 sb=0 sd=0
model=nfet_01v8_lvt
spiceprefix=X
}
C {sky130_fd_pr/nfet_01v8_lvt.sym} -160 230 1 0 {name=M139
W=7
L=1
nf=1
mult=1
ad="expr('int((@nf + 1)/2) * @W / @nf * 0.29')"
pd="expr('2*int((@nf + 1)/2) * (@W / @nf + 0.29)')"
as="expr('int((@nf + 2)/2) * @W / @nf * 0.29')"
ps="expr('2*int((@nf + 2)/2) * (@W / @nf + 0.29)')"
nrd="expr('0.29 / @W ')" nrs="expr('0.29 / @W ')"
sa=0 sb=0 sd=0
model=nfet_01v8_lvt
spiceprefix=X
}
C {sky130_fd_pr/nfet_01v8_lvt.sym} -90 230 3 1 {name=M140
W=7
L=1
nf=1
mult=1
ad="expr('int((@nf + 1)/2) * @W / @nf * 0.29')"
pd="expr('2*int((@nf + 1)/2) * (@W / @nf + 0.29)')"
as="expr('int((@nf + 2)/2) * @W / @nf * 0.29')"
ps="expr('2*int((@nf + 2)/2) * (@W / @nf + 0.29)')"
nrd="expr('0.29 / @W ')" nrs="expr('0.29 / @W ')"
sa=0 sb=0 sd=0
model=nfet_01v8_lvt
spiceprefix=X
}
C {sky130_fd_pr/nfet_01v8_lvt.sym} -20 230 1 0 {name=M141
W=7
L=1
nf=1
mult=1
ad="expr('int((@nf + 1)/2) * @W / @nf * 0.29')"
pd="expr('2*int((@nf + 1)/2) * (@W / @nf + 0.29)')"
as="expr('int((@nf + 2)/2) * @W / @nf * 0.29')"
ps="expr('2*int((@nf + 2)/2) * (@W / @nf + 0.29)')"
nrd="expr('0.29 / @W ')" nrs="expr('0.29 / @W ')"
sa=0 sb=0 sd=0
model=nfet_01v8_lvt
spiceprefix=X
}
C {lab_wire.sym} -200 250 2 0 {name=p15 sig_type=std_logic lab=VSS}
C {sky130_fd_pr/nfet_01v8_lvt.sym} -540 -530 3 1 {name=M142
W=7
L=1
nf=1
mult=1
ad="expr('int((@nf + 1)/2) * @W / @nf * 0.29')"
pd="expr('2*int((@nf + 1)/2) * (@W / @nf + 0.29)')"
as="expr('int((@nf + 2)/2) * @W / @nf * 0.29')"
ps="expr('2*int((@nf + 2)/2) * (@W / @nf + 0.29)')"
nrd="expr('0.29 / @W ')" nrs="expr('0.29 / @W ')"
sa=0 sb=0 sd=0
model=nfet_01v8_lvt
spiceprefix=X
}
C {sky130_fd_pr/nfet_01v8_lvt.sym} 120 -530 1 0 {name=M143
W=7
L=1
nf=1
mult=1
ad="expr('int((@nf + 1)/2) * @W / @nf * 0.29')"
pd="expr('2*int((@nf + 1)/2) * (@W / @nf + 0.29)')"
as="expr('int((@nf + 2)/2) * @W / @nf * 0.29')"
ps="expr('2*int((@nf + 2)/2) * (@W / @nf + 0.29)')"
nrd="expr('0.29 / @W ')" nrs="expr('0.29 / @W ')"
sa=0 sb=0 sd=0
model=nfet_01v8_lvt
spiceprefix=X
}
C {sky130_fd_pr/nfet_01v8_lvt.sym} -590 230 3 1 {name=M144
W=7
L=1
nf=1
mult=1
ad="expr('int((@nf + 1)/2) * @W / @nf * 0.29')"
pd="expr('2*int((@nf + 1)/2) * (@W / @nf + 0.29)')"
as="expr('int((@nf + 2)/2) * @W / @nf * 0.29')"
ps="expr('2*int((@nf + 2)/2) * (@W / @nf + 0.29)')"
nrd="expr('0.29 / @W ')" nrs="expr('0.29 / @W ')"
sa=0 sb=0 sd=0
model=nfet_01v8_lvt
spiceprefix=X
}
C {sky130_fd_pr/nfet_01v8_lvt.sym} 70 230 1 0 {name=M145
W=7
L=1
nf=1
mult=1
ad="expr('int((@nf + 1)/2) * @W / @nf * 0.29')"
pd="expr('2*int((@nf + 1)/2) * (@W / @nf + 0.29)')"
as="expr('int((@nf + 2)/2) * @W / @nf * 0.29')"
ps="expr('2*int((@nf + 2)/2) * (@W / @nf + 0.29)')"
nrd="expr('0.29 / @W ')" nrs="expr('0.29 / @W ')"
sa=0 sb=0 sd=0
model=nfet_01v8_lvt
spiceprefix=X
}
C {sky130_fd_pr/res_xhigh_po_1p41.sym} -250 -770 0 0 {name=R1
L=1.75
model=res_xhigh_po_1p41
spiceprefix=X
mult=1}
C {sky130_fd_pr/nfet_01v8_lvt.sym} -550 -250 1 0 {name=M122
W=7
L=1
nf=1
mult=1
ad="expr('int((@nf + 1)/2) * @W / @nf * 0.29')"
pd="expr('2*int((@nf + 1)/2) * (@W / @nf + 0.29)')"
as="expr('int((@nf + 2)/2) * @W / @nf * 0.29')"
ps="expr('2*int((@nf + 2)/2) * (@W / @nf + 0.29)')"
nrd="expr('0.29 / @W ')" nrs="expr('0.29 / @W ')"
sa=0 sb=0 sd=0
model=nfet_01v8_lvt
spiceprefix=X
}
C {sky130_fd_pr/nfet_01v8_lvt.sym} -710 -250 1 0 {name=M123
W=7
L=1
nf=1
mult=1
ad="expr('int((@nf + 1)/2) * @W / @nf * 0.29')"
pd="expr('2*int((@nf + 1)/2) * (@W / @nf + 0.29)')"
as="expr('int((@nf + 2)/2) * @W / @nf * 0.29')"
ps="expr('2*int((@nf + 2)/2) * (@W / @nf + 0.29)')"
nrd="expr('0.29 / @W ')" nrs="expr('0.29 / @W ')"
sa=0 sb=0 sd=0
model=nfet_01v8_lvt
spiceprefix=X
}
C {sky130_fd_pr/nfet_01v8_lvt.sym} -550 -30 1 1 {name=M124
W=7
L=1
nf=1
mult=1
ad="expr('int((@nf + 1)/2) * @W / @nf * 0.29')"
pd="expr('2*int((@nf + 1)/2) * (@W / @nf + 0.29)')"
as="expr('int((@nf + 2)/2) * @W / @nf * 0.29')"
ps="expr('2*int((@nf + 2)/2) * (@W / @nf + 0.29)')"
nrd="expr('0.29 / @W ')" nrs="expr('0.29 / @W ')"
sa=0 sb=0 sd=0
model=nfet_01v8_lvt
spiceprefix=X
}
C {sky130_fd_pr/nfet_01v8_lvt.sym} -710 -30 1 1 {name=M125
W=7
L=1
nf=1
mult=1
ad="expr('int((@nf + 1)/2) * @W / @nf * 0.29')"
pd="expr('2*int((@nf + 1)/2) * (@W / @nf + 0.29)')"
as="expr('int((@nf + 2)/2) * @W / @nf * 0.29')"
ps="expr('2*int((@nf + 2)/2) * (@W / @nf + 0.29)')"
nrd="expr('0.29 / @W ')" nrs="expr('0.29 / @W ')"
sa=0 sb=0 sd=0
model=nfet_01v8_lvt
spiceprefix=X
}
C {lab_wire.sym} -710 -80 0 1 {name=p16 sig_type=std_logic lab=VSS}
C {sky130_fd_pr/nfet_01v8_lvt.sym} 100 -250 3 1 {name=M146
W=7
L=1
nf=1
mult=1
ad="expr('int((@nf + 1)/2) * @W / @nf * 0.29')"
pd="expr('2*int((@nf + 1)/2) * (@W / @nf + 0.29)')"
as="expr('int((@nf + 2)/2) * @W / @nf * 0.29')"
ps="expr('2*int((@nf + 2)/2) * (@W / @nf + 0.29)')"
nrd="expr('0.29 / @W ')" nrs="expr('0.29 / @W ')"
sa=0 sb=0 sd=0
model=nfet_01v8_lvt
spiceprefix=X
}
C {sky130_fd_pr/nfet_01v8_lvt.sym} 100 -30 3 0 {name=M147
W=7
L=1
nf=1
mult=1
ad="expr('int((@nf + 1)/2) * @W / @nf * 0.29')"
pd="expr('2*int((@nf + 1)/2) * (@W / @nf + 0.29)')"
as="expr('int((@nf + 2)/2) * @W / @nf * 0.29')"
ps="expr('2*int((@nf + 2)/2) * (@W / @nf + 0.29)')"
nrd="expr('0.29 / @W ')" nrs="expr('0.29 / @W ')"
sa=0 sb=0 sd=0
model=nfet_01v8_lvt
spiceprefix=X
}
C {sky130_fd_pr/nfet_01v8_lvt.sym} 280 -250 3 1 {name=M148
W=7
L=1
nf=1
mult=1
ad="expr('int((@nf + 1)/2) * @W / @nf * 0.29')"
pd="expr('2*int((@nf + 1)/2) * (@W / @nf + 0.29)')"
as="expr('int((@nf + 2)/2) * @W / @nf * 0.29')"
ps="expr('2*int((@nf + 2)/2) * (@W / @nf + 0.29)')"
nrd="expr('0.29 / @W ')" nrs="expr('0.29 / @W ')"
sa=0 sb=0 sd=0
model=nfet_01v8_lvt
spiceprefix=X
}
C {lab_wire.sym} 310 -190 0 1 {name=p17 sig_type=std_logic lab=VSS}
C {sky130_fd_pr/nfet_01v8_lvt.sym} 350 -30 3 0 {name=M149
W=7
L=1
nf=1
mult=1
ad="expr('int((@nf + 1)/2) * @W / @nf * 0.29')"
pd="expr('2*int((@nf + 1)/2) * (@W / @nf + 0.29)')"
as="expr('int((@nf + 2)/2) * @W / @nf * 0.29')"
ps="expr('2*int((@nf + 2)/2) * (@W / @nf + 0.29)')"
nrd="expr('0.29 / @W ')" nrs="expr('0.29 / @W ')"
sa=0 sb=0 sd=0
model=nfet_01v8_lvt
spiceprefix=X
}
C {lab_wire.sym} 400 -80 0 1 {name=p19 sig_type=std_logic lab=VSS}
